// TwinCAT 3 PLC project First_Recipe_Save
// libraries:
//   Lib_FileOperation, * (Beckhoff China)
//   Tc2_Standard, * (Beckhoff Automation GmbH)
//   Tc2_Standard, * (Beckhoff Automation GmbH)
//   Tc2_System, * (Beckhoff Automation GmbH)
//   Tc2_System, * (Beckhoff Automation GmbH)
//   Tc2_Utilities, * (Beckhoff Automation GmbH)
//   Tc2_XmlDataSrv, * (Beckhoff Automation GmbH)
//   Tc3_Module, * (Beckhoff Automation GmbH)
//   Tc3_Module, * (Beckhoff Automation GmbH)
// project tree:
//   Data types/Recipe_MachineData/ ST_MachineData.TcDUT, ST_RecData.TcDUT
//   Global Variables/ Global_Variables.TcGVL, Global_Variables_Param.TcGVL, Variable_Configuration.TcGVL
//   Global Variables/Recipe_Var_and_Constant/ Recipe_Manager.TcGVL, Recipe_OtherHMI.TcGVL
//   / GlobalImagePool.TcGIPO, GlobalTextList.TcGTLO, PlcTask1.TcTTO, 视图管理器.TcVMO
//   POUs/FileOperation/File FB/Backup/ FB_MachineData_BIN.TcPOU, FB_MachineData_XML.TcPOU
//   POUs/FileOperation/File FB/ FB_MachineData.TcPOU
//   POUs/FileOperation/File PRG/ PRG_MachineDataSave.TcPOU
//   POUs/FileOperation/Recipe FB/ FB_Recipe.TcPOU, FB_Recipe_OtherHMI.TcPOU, FB_Recipe_TcPlcHMI.TcPOU
//   POUs/FileOperation/Recipe PRG/ PRG_Recipe.TcPOU, PRG_Recipe_OtherHMI.TcPOU, PRG_Recipe_TcPlcHMI.TcPOU
//   POUs/ MAIN.TcPOU, P099_Call_Recipe.TcPOU
//   Visualizations/9_FBs & FCs/Files Operation/Recipe/PH/V2/Button/ PH_RECIPE_BUTTON_DELETE_2.TcVIS, PH_RECIPE_BUTTON_FLASH_2.TcVIS, PH_RECIPE_BUTTON_FROM_USB_2.TcVIS, PH_RECIPE_BUTTON_LOAD_2.TcVIS, PH_RECIPE_BUTTON_SAVE_2.TcVIS, PH_RECIPE_BUTTON_SAVE_AS_2.TcVIS, PH_RECIPE_BUTTON_TO_USB_2.TcVIS
//   Visualizations/9_FBs & FCs/Files Operation/Recipe/PH/V2/Confirm Windows/ PH_RECIPE_CONFIRM_WINDOW_2.TcVIS
//   Visualizations/9_FBs & FCs/Files Operation/Recipe/PH/V2/Files Name/ PH_RECIPE_CURRENT_OPEN_FILE_2.TcVIS, PH_RECIPE_FILE_PATH_2.TcVIS, PH_RECIPE_LOAD_FILE_NAME_2.TcVIS, PH_RECIPE_SAVE_FILE_NAME_2.TcVIS
//   Visualizations/9_FBs & FCs/Files Operation/Recipe/PH/V2/Recipe Name/ PH_RECIPE_FILE_NAME_DISPLAY_1.TcVIS, PH_RECIPE_FILE_NAME_DISPLAY_2.TcVIS
//   Visualizations/9_FBs & FCs/Files Operation/Recipe/PH/V2/Scroll/ PH_RECIPE_PAGE_BOTTON_2.TcVIS, PH_RECIPE_PAGE_DOWN_2.TcVIS, PH_RECIPE_PAGE_TOP_2.TcVIS, PH_RECIPE_PAGE_UP_2.TcVIS, PH_RECIPE_REGULAR.TcVIS, PH_RECIPE_REGULAR_1.TcVIS, PH_RECIPE_SCROLL_DOWN_2.TcVIS, PH_RECIPE_SCROLL_UP_2.TcVIS
//   Visualizations/9_FBs & FCs/Files Operation/Recipe/ question.TcTLO, SystemDisplay.TcTLO, TextList_Recipe.TcTLO
//   Visualizations/9_FBs & FCs/Payment/ PH_PAYMENT_CTRL.TcVIS, TextList_Payment.TcTLO
//   Visualizations/Demo_Recipe_HMI/ BECKHOFF_PLC_HMI.TcVIS, THIRDPARTY_HMI.TcVIS

CONFIGURATION First_Recipe_Save
    RESOURCE PLC ON TwinCAT3
        TASK PlcTask1(INTERVAL := T#2ms, PRIORITY := 22);
        PROGRAM P099_Call_Recipe WITH PlcTask1 : P099_Call_Recipe;
    END_RESOURCE
END_CONFIGURATION

// ---- Data types/Recipe_MachineData/ST_MachineData.TcDUT
TYPE ST_MachineData :		(*机器参数, 只保存一个文件*)
STRUCT
	MacData1		: ARRAY[1..2] OF LREAL;
	MacData2		: ARRAY[1..2] OF INT;
	MacData3		: ARRAY[1..2] OF BOOL;

END_STRUCT
END_TYPE

// ---- Data types/Recipe_MachineData/ST_RecData.TcDUT
TYPE ST_RecData :			(*配方参数, 不同配方参数, 保存在不同的文件中*)
STRUCT

(*设置参数*)
	rTemp:REAL:=120;      	(*温度，120.C*)
	rSpeedRpm:REAL:=3000;(*速度，3000rpm*)
	rPressure:REAL:=9.8; (*压力，9.8kg*)

END_STRUCT
END_TYPE

// ---- Global Variables/Global_Variables.TcGVL
{attribute 'Tc2GvlVarNames'}
VAR_GLOBAL
END_VAR

// ---- Global Variables/Global_Variables_Param.TcGVL
{attribute 'Tc2GvlVarNames'}
VAR_GLOBAL
	sRecData				: ST_RecData;
	sMacData				: ST_MachineData;

(*临时变量, 和设置的参数比较, 参数修改后, 延时自动保存参数*)
(*结构体类型(数组长度)必须一致, 否则比较/复制时, 会有意想不到的错误*)
	_sRecData				: ST_RecData;
	_sMacData				: ST_MachineData;
END_VAR

// ---- Global Variables/Recipe_Var_and_Constant/Recipe_Manager.TcGVL
{attribute 'Tc2GvlVarNames'}
(*配方功能相关变量*)
VAR_GLOBAL
	g_sRecipeCtrl				: ST_RecipeCtrl_2;
END_VAR

VAR_GLOBAL CONSTANT
	MAX_RECIPE_NUM				: INT := 15;	(*配方列表中显示的文件数量*)
	MAX_RECIPE_DATA				: INT := 2;	(*配方变量(一个结构、数组只算一个变量, 离散的)*)
END_VAR

// ---- Global Variables/Recipe_Var_and_Constant/Recipe_OtherHMI.TcGVL
{attribute 'Tc2GvlVarNames'}
(*配方功能: 第三方触摸屏*)

VAR_GLOBAL CONSTANT
	MAX_FILE_NAME_STR			: INT	:= 20;	(*配方名字长度, 20个字节*)
	MAX_RECIPE_FILES			: INT	:= 5;	(*最多保存的配方数量*)
END_VAR

VAR_GLOBAL
(*配方文件(和配方号对应的)名字*)
	H_RecipeName				: ARRAY[0..MAX_RECIPE_FILES] OF STRING(MAX_FILE_NAME_STR);
END_VAR

VAR_GLOBAL
	H_CurRecipeNum				: INT;	(*当前配方号*)
	H_SetRecipeNum				: INT;	(*设定配方号, 0~100*)
(*!!!按钮, 下降沿触发!!!*)
	H_RecipeLoad				: BOOL;	(*读取设定配方号中的参数*)
	H_RecipeSave				: BOOL;	(*参数保存到当前配方号*)
	H_RecipeSaveAs				: BOOL;	(*参数保存到设定的配方号*)
(*状态*)
	H_RecipeInitialDone			: BOOL;	(*初始化完成*)
	H_RecipeDone				: BOOL;	(*读写完成*)
	H_RecipeBusy				: BOOL;	(*读写中*)
	H_RecipeError				: BOOL;	(*读写失败*)
	H_RecipeLoading				: BOOL;	(*配方读取中...*)
	H_RecipeSaving				: BOOL;	(*配方保存中...*)
	H_NewRecipeSaving			: BOOL;	(*配方另存中...*)
	H_CurDataAutoSaving			: BOOL;	(*自动保存中...*)
(*当前配方名*)
	H_CurRecName				: STRING(MAX_FILE_NAME_STR);
END_VAR

// ---- Global Variables/Variable_Configuration.TcGVL
{attribute 'Tc2GvlVarNames'}
VAR_CONFIG
END_VAR

// ---- POUs/P099_Call_Recipe.TcPOU
PROGRAM P099_Call_Recipe
VAR
	bThirdpartyHMI			: BOOL;
	iHMI: INT;
END_VAR



(*保存机器数据*)
PRG_MachineDataSave();

CASE iHMI OF

1:(*使用TwinCAT PLC HMI 操作配方*)
	PRG_Recipe_TcPlcHMI();

2:(*使用第三方触摸屏操作配方*)
	PRG_Recipe_OtherHMI();

ELSE
  (*没有配方操作的界面*)
	PRG_Recipe();

END_CASE

END_PROGRAM

// ---- POUs/FileOperation/File PRG/PRG_MachineDataSave.TcPOU
PROGRAM PRG_MachineDataSave	(*只做参数保存, 没有配方, 需要输入一个文件名(如果有重复, 会把旧文件删除, 会影响其他参数!!), 多个变量要保存成多个文件(名)!!*)
VAR
	fbMachineData		: FB_MachineData;
	eFileType			: E_FileType :=eFileType_BIN;
END_VAR

;
fbMachineData(
	bRunOnCeDevice		:= FALSE,					(* TRUE--CE系统, FALSE--非CE系统*)
	sgFilePath			:= ,						(* 文件路径, 默认是 \Data\Machine\' *)
	sgFileName			:= 'MachineData',			(* 文件名 *)
	eFileType			:= eFileType,
	pMacData			:= ADR(sMacData),			(* 机械参数首地址 *)
	pBakData			:= ADR(_sMacData),			(* 机械参数备份的首地址, 保存上一次的参数值, 用来比较参数是否有变化 *)
	nMacSize			:= SIZEOF(sMacData),		(* 机械参数总字节数 *)
	tAutoSave			:= T#10S,					(* 参数变化后, 延时保存(写文件) *)
	bInitialDone		=> ,
	bDone				=> ,
	bBusy				=> ,
	bError				=> );

END_PROGRAM

// ---- POUs/FileOperation/File FB/FB_MachineData.TcPOU
FUNCTION_BLOCK FB_MachineData
VAR_INPUT
	bRunOnCeDevice				: BOOL	:= TRUE;	(*在CE系统运行*)
	sgFilePath					: STRING(255)	:= 'Data\Machine\';	(*文件路径*)
	sgFileName					: STRING(255)	:= 'Test';			(*文件名*)
	eFileType					: E_FileType	:= eFileType_XML;	(*文件类型, 只支持 eFileType_XML 和 eFileType_BIN 两种类型*)
(*参数和备份(用来比较参数是否修改的)的类型必须一致, 把两个变量的首地址和数据长度传到功能块*)
	pMacData					: PVOID;			(*配方首地址*)
	pBakData					: PVOID;			(*配方备份数据首地址, 数据类型必须和配方一样*)
	nMacSize					: UDINT;			(*配方的字节数*)
	tAutoSave					: TIME	:= T#10S;	(*配方改变后, 延时保存*)
END_VAR
VAR_OUTPUT
(*状态*)
	bInitialDone				: BOOL;	(*初始化完成*)
	bDone						: BOOL;
	bBusy						: BOOL;
	bError						: BOOL;
END_VAR
VAR		
	eStep						: INT;
(*Last status*)
	s_sLastExecuteResult		: ST_LastExecutionResult_File;
(*FB*)
	s_fbWriteReadFileXml		: FB_WriteReadFileXML_ByAddr;
	s_fbWriteReadFileBin		: FB_WriteReadFileBIN_2;
	s_nErrorCounter				: UDINT;
(*参数改变, 延时触发写文件*)
	s_tonDataChange				: TON;
	s_bDataChange				: BOOL;
	s_bManualWriteOnce			: BOOL;
	s_fbWriteReadFile: BOOL;
END_VAR

(*==================================================================
配置
==================================================================*)
	s_tonDataChange.PT					:= tAutoSave;		(*参数修改后, 延时写入临时文件(作用是掉电保持)的时间*)


(*==================================================================
变量地址是否有误
==================================================================*)
IF pMacData = 0 OR nMacSize <= 0 OR pBakData = 0 THEN
	bInitialDone := bBusy := bDone := FALSE;
	eStep := 0;
	bError := TRUE;
	RETURN;
END_IF


(*==================================================================
判断参数是否变化, 变化后, 延时写入文件
==================================================================*)
(*参数比较, 有变化时, 延时置位s_bDataChange, 将当前参数写到临时文件中*)
IF pMacData <> 0 AND nMacSize > 0 AND pBakData <> 0 THEN
	IF MEMCMP(pBakData, pMacData, nMacSize) <> 0 THEN
		s_tonDataChange(IN := FALSE);		(*重新计时*)
		s_tonDataChange(IN := bInitialDone);	(*上载配方后, 只复制参数, 不写入临时文件*)
		MEMCPY(pBakData, pMacData, nMacSize);	(*比较不同, 重新定时, 并把数据复制到局部变量*)
	END_IF
ELSE
	bInitialDone := FALSE;
END_IF

s_tonDataChange();

s_bDataChange := FALSE;
IF s_tonDataChange.Q THEN
	s_tonDataChange(IN := FALSE);
	s_bDataChange := TRUE;
END_IF


(*保存路径*)
CASE eFileType OF
	eFileType_BIN:
		IF bRunOnCeDevice THEN
			s_fbWriteReadFileBin.sgDeviceName	:= '\Hard disk\';
		ELSE
			s_fbWriteReadFileBin.sgDeviceName	:= 'C:\';
		END_IF
			s_fbWriteReadFileBin.sgFolderName	:= sgFilePath;
			s_fbWriteReadFileBin.sgNetId		:= '';
			s_fbWriteReadFileBin.sOption.bSameAddress_RW	:= FALSE;
			s_fbWriteReadFileBin.sOption.sBinHeader.bInused	:= FALSE;
	ELSE
		IF bRunOnCeDevice THEN
			s_fbWriteReadFileXml.sgFilePath	:= '\Hard disk\';
		ELSE
			s_fbWriteReadFileXml.sgFilePath	:= 'C:\';
		END_IF
			s_fbWriteReadFileXml.sgFilePath	:= F_CreatePath(s_fbWriteReadFileXml.sgFilePath, sgFilePath, '', '');
END_CASE

(*读写流程*)
CASE eStep OF
	0:
		bDone := bError := FALSE;
		IF NOT bInitialDone THEN
			MEMSET(ADR(s_sLastExecuteResult), 0, SIZEOF(s_sLastExecuteResult));
			s_fbWriteReadFileXml(bReadFile := FALSE, bWriteFile := FALSE);
			s_fbWriteReadFileBin(bReadFile := FALSE, bWriteFile := FALSE);
			CASE eFileType OF
				eFileType_BIN:
					eStep := 100;
				ELSE
					eStep := 150;
			END_CASE
		ELSE
			IF s_bDataChange					(*数据变化后, 延时写入*)
			OR s_bManualWriteOnce THEN			(*手动写入一次(测试用)*)
				MEMSET(ADR(s_sLastExecuteResult), 0, SIZEOF(s_sLastExecuteResult));
				s_bDataChange := FALSE;
				s_bManualWriteOnce := FALSE;
				s_fbWriteReadFileXml(bReadFile := FALSE, bWriteFile := FALSE);
				s_fbWriteReadFileBin(bReadFile := FALSE, bWriteFile := FALSE);
				CASE eFileType OF
					eFileType_BIN:
						eStep := 200;
					ELSE
						eStep := 250;
				END_CASE
			END_IF
		END_IF

	100:	(*读取BIN文件*)
		s_fbWriteReadFileBin.pDestBuffer	:= pMacData;
		s_fbWriteReadFileBin.u32DestSize	:= nMacSize;
		s_fbWriteReadFileBin.sgFileName		:= sgFileName;
		s_fbWriteReadFileBin(bReadFile := TRUE);
		s_nErrorCounter					:= 0;
		eStep := 110;
	110:
		s_fbWriteReadFileBin(bReadFile := TRUE);
		IF NOT s_fbWriteReadFileBin.bBusy THEN
			IF NOT s_fbWriteReadFileBin.bError THEN
				MEMCPY(pBakData, pMacData, nMacSize);	(*读取完, 把值传给中间变量*)
				bDone := TRUE;
				eStep := 0;
			ELSE
				s_nErrorCounter := s_nErrorCounter + 1;	(*连续读写失败, 可能是文件不存在, 跳过*)
				IF s_nErrorCounter > 5 THEN
					bError := TRUE;
					eStep := 0;
				END_IF
			END_IF
			s_bDataChange := FALSE;
			s_bManualWriteOnce := FALSE;
			s_fbWriteReadFileBin(bReadFile := FALSE, bWriteFile := FALSE);
		END_IF

	150:	(*读取XML文件*)
		s_fbWriteReadFileXml.pDataADR		:= pMacData;
		s_fbWriteReadFileXml.u32DataSIZEOF	:= nMacSize;
		s_fbWriteReadFileXml.sgFileName		:= sgFileName;
		s_fbWriteReadFileXml(bReadFile := TRUE);
		s_nErrorCounter					:= 0;
		eStep := 160;
	160:
		s_fbWriteReadFileXml(bReadFile := TRUE);
		IF NOT s_fbWriteReadFileXml.bBusy THEN
			IF NOT s_fbWriteReadFileXml.bError THEN
				MEMCPY(pBakData, pMacData, nMacSize);	(*读取完, 把值传给中间变量*)
				bDone := TRUE;
				eStep := 0;
			ELSE
				s_nErrorCounter := s_nErrorCounter + 1;	(*连续读写失败, 可能是文件不存在, 跳过*)
				IF s_nErrorCounter > 5 THEN
					bError := TRUE;
					eStep := 0;
				END_IF
			END_IF
			s_bDataChange := FALSE;
			s_bManualWriteOnce := FALSE;
			s_fbWriteReadFileXml(bReadFile := FALSE, bWriteFile := FALSE);
		END_IF

	200:	(*写入BIN文件*)
		s_fbWriteReadFileBin.pSrcBuffer		:= pMacData;
		s_fbWriteReadFileBin.u32SrcSize		:= nMacSize;
		s_fbWriteReadFileBin.sgFileName		:= sgFileName;
		s_fbWriteReadFileBin(bWriteFile := TRUE);
		eStep := 210;
	210:
		s_fbWriteReadFileBin(bWriteFile := TRUE);
		IF s_fbWriteReadFileBin.bWriteFile THEN
			s_fbWriteReadFileBin(bWriteFile := TRUE);
			IF NOT s_fbWriteReadFileBin.bBusy THEN
				IF NOT s_fbWriteReadFileBin.bError THEN
					bDone := TRUE;
				ELSE
					bError := TRUE;
				END_IF
				s_fbWriteReadFileBin(bReadFile := FALSE, bWriteFile := FALSE);
				eStep := 0;
			END_IF
		END_IF
	250:	(*写入XML文件*)
		s_fbWriteReadFileXml.pDataADR		:= pMacData;
		s_fbWriteReadFileXml.u32DataSIZEOF	:= nMacSize;
		s_fbWriteReadFileXml.sgFileName		:= sgFileName;
		s_fbWriteReadFileXml(bWriteFile := TRUE);
		eStep := 260;
	260:
		s_fbWriteReadFileXml(bWriteFile := TRUE);
		IF s_fbWriteReadFileXml.bWriteFile THEN
			s_fbWriteReadFileXml(bWriteFile := TRUE);
			IF NOT s_fbWriteReadFileXml.bBusy THEN
				IF NOT s_fbWriteReadFileXml.bError THEN
					bDone := TRUE;
				ELSE
					bError := TRUE;
				END_IF
				s_fbWriteReadFileXml(bReadFile := FALSE, bWriteFile := FALSE);
				eStep := 0;
			END_IF
		END_IF
END_CASE


IF eStep <> 0 THEN
	bBusy := TRUE;
ELSE
	IF bBusy THEN
		bBusy := FALSE;
		bInitialDone := TRUE;			(*不管有没有读取成功, 都认为初始化完成*)
		s_sLastExecuteResult.bDone := bDone;
		s_sLastExecuteResult.bError := bError;
	END_IF
END_IF

END_FUNCTION_BLOCK

// ---- POUs/FileOperation/Recipe PRG/PRG_Recipe_TcPlcHMI.TcPOU
PROGRAM PRG_Recipe_TcPlcHMI	(*Twincat PLC HMI, 参数保存, 配方功能*)
VAR
	fbRecipeTcPlcHMI	: FB_Recipe_TcPlcHMI;
	eFileType			: E_FileType :=eFileType_BIN;
END_VAR


(*测试*)
VAR
	nErrorCounter			: INT;
	nDoneCounter			: INT;
END_VAR

;
fbRecipeTcPlcHMI(
	bRunOnCeDevice		:= FALSE,					(* TRUE--CE系统, FALSE--非CE系统*)
	sgFilePath			:= '\Data\Recipe\',			(* 文件路径, 默认是 \Data\Recipe\' *)
	eFileType			:= eFileType ,				(* 文件类型, 默认是XML, 只支持 eFileType_XML 和 eFileType_BIN 两种类型 *)
	pRecData			:= ADR(sRecData),			(* 配方参数首地址 *)
	pBakData			:= ADR(_sRecData),			(* 配方备份的首地址, 保存上一次的参数值, 用来比较参数是否有变化 *)
	nRecSize			:= SIZEOF(sRecData),		(* 配方总字节数 *)
	tAutoSaveRec		:= T#3S,					(* 参数变化后, 延时保存(写文件) *)
	sRecipeCtrl			:= g_sRecipeCtrl,			(* 触摸屏按钮, 配方名, 状态等等 *)
	bInitialDone		=> ,						(* 初始化完成 *)
	bDone				=> ,						(* 读写完成 *)
	bBusy				=> ,						(* 读写中 *)
	bError				=> ,						(* 读写失败 *)
	nErrorId			=> );						(* 错误代码 *)


(*测试*)
IF fbRecipeTcPlcHMI.bError THEN		(*没有作用, 要读取 LastResult.Error*)
	nErrorCounter := nErrorCounter + 1;
END_IF
IF fbRecipeTcPlcHMI.bDone THEN
	nDoneCounter := nDoneCounter + 1;
END_IF

END_PROGRAM

// ---- POUs/FileOperation/Recipe FB/FB_Recipe_TcPlcHMI.TcPOU
FUNCTION_BLOCK FB_Recipe_TcPlcHMI
VAR_INPUT
	bRunOnCeDevice				: BOOL	:= TRUE;	(*在CE系统运行*)
	sgFilePath					: STRING(255)	:= 'Data\Recipe\';	(*文件路径*)
	eFileType					: E_FileType	:= eFileType_XML;	(*文件类型, 只支持 eFileType_XML 和 eFileType_BIN 两种类型*)
(*配方和备份(用来比较配方参数是否修改的)的类型必须一致, 把两个变量的首地址和数据长度传到功能块*)
	pRecData					: PVOID;			(*配方首地址*)
	pBakData					: PVOID;			(*配方备份数据首地址, 数据类型必须和配方一样*)
	nRecSize					: UDINT;			(*配方的字节数*)
	tAutoSaveRec				: TIME	:= T#10S;	(*配方改变后, 延时保存*)
END_VAR
VAR_OUTPUT
(*状态*)
	bInitialDone				: BOOL;	(*初始化完成*)
	bDone						: BOOL;
	bBusy						: BOOL;
	bError						: BOOL;
	nErrorId					: UDINT;
END_VAR
VAR_IN_OUT
	sRecipeCtrl					: ST_RecipeCtrl_2;	(*配方相关的命令和状态*)
END_VAR
VAR
	i: INT;
(*Last status*)
	s_sLastExecuteResult		: ST_LastExecutionResult_File;
(*FB*)
	s_fbRecipeManager			: FB_RecipeManager_2;
	s_sRecipeData				: ST_RecipeData_2;
(*上载配方动作, 上载完成后, 不判断当前参数是否有改变*)
	s_ftRecipeLoad				: F_TRIG;
	s_tonLoadRecipe				: TON;
(*参数改变, 延时触发写文件*)
	s_tonDataChange				: TON;
	s_bDataChange				: BOOL;
(*配方读写时间*)
	s_tActRecipeRead			: TIME;
	s_tActRecipeWrite			: TIME;
	s_tRecipeRead				: TIME;
	s_tRecipeWrite				: TIME;
	s_tonRecipeOperation		: TON;
	s_tonRecipeNotBusy			: TON;
END_VAR

;
(*==================================================================
配置
==================================================================*)
	(*延时时间*)
	s_tonDataChange.PT					:= tAutoSaveRec;		(*参数修改后, 延时写入临时文件(作用是掉电保持)的时间*)
	s_tonLoadRecipe.PT					:= T#100MS;		(*上载配方时, 延时判断读取完成*)

	(*其他, 只针对TwinCAT PLC HMI, 第三方触摸屏的可以不设置*)
	sRecipeCtrl.i16DisplayFilesNum		:= 14;			(*Target Visualization中用到的'PH_RECIPE_FILE_NAME_DISPLAY'的数量, 如果是第三方HMI, 设置为0*)
	sRecipeCtrl.bRecipeNeedConfirm		:= TRUE;		(*上载, 保存, 删除是否需要确认. FALSE--不需要, TRUE--需要, 第三方触摸屏, 建议设置为FALSE*)	(*2020.10.10, 更改为FALSE*)
	sRecipeCtrl.bRecipeAutoRead			:= TRUE;		(*初始化时, 是否要从actRecipe中读取之前保存的参数*)
	sRecipeCtrl.bFileTypeDisplay		:= FALSE;		(*在'PH_RECIPE_FILE_NAME_DISPLAY'是否显示文件类型. FALSE--不显示, TRUE--显示*)
(*
	sRecipeCtrl.u16MaxTempFilesNum		:= 300;			(*保存300个临时文件*)
	sRecipeCtrl.u16KeepErrorFilesDay	:= 7;			(*错误文件保存7天*)
*)



(*==================================================================
变量地址是否有误
==================================================================*)
IF pRecData = 0 OR nRecSize <= 0 OR pBakData = 0 THEN
	bInitialDone := bBusy := bDone := FALSE;
	bError := TRUE;
	IF nRecSize > 0 THEN
		nErrorId := 16#5F0A;
	ELSE
		nErrorId := 16#5F0B;
	END_IF
	RETURN;
END_IF
(*变量的地址和长度*)
s_sRecipeData.stRecipeDataArr[1].pRecipeDataInfoADR			:= pRecData;
s_sRecipeData.stRecipeDataArr[1].u32RecipeDataInfoSIZEOF	:= nRecSize;
s_sRecipeData.stRecipeDataArr[1].sgRecipeDataInfoName		:= 'RecData';


(*==================================================================
判断参数是否变化, 变化后, 延时写入文件
==================================================================*)
s_tonRecipeNotBusy(IN := NOT sRecipeCtrl.sStatus.bBusy, PT := T#1S);
(*上载配方完成后, 把当前参数复制到临时参数中. 不写文件*)
s_ftRecipeLoad(CLK := sRecipeCtrl.sCmd.bRecipeLoad);
IF s_ftRecipeLoad.Q THEN
	s_tonLoadRecipe.IN := TRUE;
END_IF
s_tonLoadRecipe();
IF s_tonLoadRecipe.Q AND s_tonRecipeNotBusy.Q THEN
	s_tonLoadRecipe(IN := FALSE);
	s_tonDataChange(IN := FALSE);
END_IF

(*参数比较, 有变化时, 延时置位s_bDataChange, 将当前参数写到临时文件中*)
IF pRecData <> 0 AND nRecSize > 0 AND pBakData <> 0 THEN
	IF MEMCMP(pBakData, pRecData, nRecSize) <> 0 THEN
		s_tonDataChange(IN := FALSE);		(*重新计时*)
		s_tonDataChange(IN := sRecipeCtrl.sStatus.bInitialOk AND s_tonRecipeNotBusy.Q);	(*上载配方后, 只复制参数, 不写入临时文件*)
		MEMCPY(pBakData, pRecData, nRecSize);	(*比较不同, 重新定时, 并把数据复制到局部变量*)
	END_IF
END_IF

s_tonDataChange();
s_bDataChange := FALSE;
IF s_tonDataChange.Q AND s_tonRecipeNotBusy.Q THEN
	s_tonDataChange(IN := FALSE);
	s_bDataChange := TRUE;
END_IF

(*文件类型*)
IF eFileType = eFileType_BIN THEN
	s_fbRecipeManager.eFileType	:= eFileType_BIN;
ELSE
	s_fbRecipeManager.eFileType	:= eFileType_XML;
END_IF


(*==================================================================
调用配方程序, 根据实际情况修改文件夹路径: sgFolderName 和文件类型 eFileType
==================================================================*)
s_fbRecipeManager(
	sRecipeData				:= s_sRecipeData,		(*配方*)
	sgNetId					:= '',
	sgDeviceName			:= SEL(bRunOnCeDevice, 'C:\', '\Hard disk\'),		(*Device*)
	sgUsbDeviceName			:= SEL(bRunOnCeDevice, 'D:\', '\Hard disk2\'),		(*USB*)
	sgFolderName			:= sgFilePath,			(*文件夹, 支持多重, 写入时自动新建文件夹*)
	eFileType				:= ,					(*文件类型, 只支持 BIN 和 XML 两种类型*)
	bDataChange				:= s_bDataChange,		(*配方数据变更, 如果启用自动读取功能, 参数改变后, 会写到临时文件 actRecipe中, 掉电保持*)
	sRecipeCtrl				:= sRecipeCtrl);		(*和HMI的接口(按钮, 状态等)*)



(*记录读写时间*)
IF sRecipeCtrl.sStatus.bBusy THEN
	s_tonRecipeOperation(IN := TRUE, PT := T#1H);
	CASE s_fbRecipeManager.s_eOperateStep OF
		1..99:
			s_tActRecipeRead := s_tonRecipeOperation.ET;
		200..299:
			s_tActRecipeWrite := s_tonRecipeOperation.ET;
		300..399:
			s_tRecipeRead := s_tonRecipeOperation.ET;
		400..499:
			s_tRecipeWrite := s_tonRecipeOperation.ET;
	END_CASE
ELSE
	s_tonRecipeOperation(IN := FALSE);
	sRecipeCtrl.sStatus.bError := FALSE;
END_IF

(*状态*)
bInitialDone	:= sRecipeCtrl.sStatus.bInitialOk;	(*初始化完成*)
bError			:= sRecipeCtrl.sStatus.bError;		(*报错*)
bBusy			:= sRecipeCtrl.sStatus.bBusy;
bDone			:= sRecipeCtrl.sStatus.bDone;
nErrorId		:= sRecipeCtrl.sStatus.u32ErrorId;
(*上一次触发的状态*)
MEMCPY(ADR(s_sLastExecuteResult), ADR(s_fbRecipeManager.s_sLastExecuteResult), SIZEOF(s_sLastExecuteResult));

END_FUNCTION_BLOCK

// ---- POUs/FileOperation/Recipe PRG/PRG_Recipe_OtherHMI.TcPOU
PROGRAM PRG_Recipe_OtherHMI	(*第三方触摸屏, 参数保存, 配方功能*)
VAR
	fbRecipeOtherHMI		: FB_Recipe_OtherHMI;
	eFileType			: E_FileType :=eFileType_BIN;
END_VAR


(*测试*)
VAR
	nErrorCounter			: INT;
	nDoneCounter			: INT;
END_VAR

;
fbRecipeOtherHMI(
	bRunOnCeDevice		:= FALSE,					(* TRUE--CE系统, FALSE--非CE系统*)
	sgFilePath			:= ,						(* 文件路径, 默认是 \Data\Recipe\' *)
	eFileType			:= eFileType,						(* 文件类型, 默认是XML, 只支持 eFileType_XML 和 eFileType_BIN 两种类型 *)
	pRecData			:= ADR(sRecData),			(* 配方参数首地址 *)
	pBakData			:= ADR(_sRecData),			(* 配方备份的首地址, 保存上一次的参数值, 用来比较参数是否有变化 *)
	nRecSize			:= SIZEOF(sRecData),		(* 配方总字节数 *)
	tAutoSaveRec		:= T#10S,					(* 参数变化后, 延时保存(写文件) *)
	H_RecipeLoad		:= H_RecipeLoad,			(* 第三方触摸屏上的 读取配方 按钮 *)
	H_RecipeSave		:= H_RecipeSave,			(* 第三方触摸屏上的 保存配方 按钮 *)
	H_RecipeSaveAs		:= H_RecipeSaveAs,			(* 第三方触摸屏上的 另存配方 按钮 *)
	H_SetRecipeNum		:= H_SetRecipeNum,			(* 第三方触摸屏上的 读写配方号 *)
	H_RecipeName		:= H_RecipeName,			(* 第三方触摸屏上的 配方名(输入输出接口) *)
	H_CurRecipeNum		=> H_CurRecipeNum,			(* 当前配方号 *)
	H_CurRecName		=> H_CurRecName,			(* 当前配方名 *)
	H_RecipeInitialDone	=> H_RecipeInitialDone,		(* 初始化完成 *)
	H_RecipeDone		=> H_RecipeDone,			(* 读写完成 *)
	H_RecipeBusy		=> H_RecipeBusy,			(* 读写中 *)
	H_RecipeError		=> H_RecipeError,			(* 读写失败 *)
	H_RecipeLoading		=> H_RecipeLoading,			(* 读取配方中 *)
	H_RecipeSaving		=> H_RecipeSaving,			(* 保存配方中 *)
	H_NewRecipeSaving	=> H_NewRecipeSaving,		(* 另存配方中 *)
	H_CurDataAutoSaving	=> H_CurDataAutoSaving);	(* 自动保存中 *)


(*测试*)
IF H_RecipeError THEN
	nErrorCounter := nErrorCounter + 1;
END_IF
IF H_RecipeDone THEN
	nDoneCounter := nDoneCounter + 1;
END_IF

END_PROGRAM

// ---- POUs/FileOperation/Recipe FB/FB_Recipe_OtherHMI.TcPOU
FUNCTION_BLOCK FB_Recipe_OtherHMI
VAR_INPUT
	bRunOnCeDevice				: BOOL	:= TRUE;	(*在CE系统运行*)
	sgFilePath					: STRING(255)	:= 'Data\Recipe\';	(*文件路径*)
	eFileType					: E_FileType	:= eFileType_XML;	(*文件类型, 只支持 eFileType_XML 和 eFileType_BIN 两种类型*)
(*配方和备份(用来比较配方参数是否修改的)的类型必须一致, 把两个变量的首地址和数据长度传到功能块*)
	pRecData					: PVOID;			(*配方首地址*)
	pBakData					: PVOID;			(*配方备份数据首地址, 数据类型必须和配方一样*)
	nRecSize					: UDINT;			(*配方的字节数*)
	tAutoSaveRec				: TIME	:= T#10S;	(*配方改变后, 延时保存*)

(*按钮, 下降沿触发!!!*)
	H_RecipeLoad				: BOOL;	(*读取设定配方号中的参数*)
	H_RecipeSave				: BOOL;	(*参数保存到当前配方号*)
	H_RecipeSaveAs				: BOOL;	(*参数保存到设定的配方号*)
(*设定配方号*)
	H_SetRecipeNum				: INT	:= 1;	(*设定配方号, 1~100*)
END_VAR
VAR_OUTPUT
(*当前配方号*)
	H_CurRecipeNum				: INT;
(*配方文件(和配方号对应的)名字*)
	H_CurRecName				: STRING(20);
(*状态*)
	H_RecipeInitialDone			: BOOL;	(*初始化完成*)
	H_RecipeDone				: BOOL;	(*读写完成*)
	H_RecipeBusy				: BOOL;	(*读写中*)
	H_RecipeError				: BOOL;	(*读写失败*)
	H_RecipeLoading				: BOOL;	(*配方读取中...*)
	H_RecipeSaving				: BOOL;	(*配方保存中...*)
	H_NewRecipeSaving			: BOOL;	(*配方另存中...*)
	H_CurDataAutoSaving			: BOOL;	(*自动保存中...*)
END_VAR
VAR_IN_OUT
	H_RecipeName				: ARRAY[0..MAX_RECIPE_FILES] OF STRING(MAX_FILE_NAME_STR);	(*0存放配方号, 1~MAX, 存放配方名字*)
END_VAR
VAR
	i: INT;
(*Last status*)
	s_sLastExecuteResult		: ST_LastExecutionResult_File;
(*FB*)
	s_fbRecipeManager			: FB_RecipeManager_2;
	s_sRecipeData				: ST_RecipeData_2;
	s_sRecipeCtrl				: ST_RecipeCtrl_2;	(*配方相关的命令和状态*)
(*上载配方动作, 上载完成后, 不判断当前参数是否有改变*)
	s_ftRecipeLoad				: F_TRIG;
	s_tonLoadRecipe				: TON;
(*参数改变, 延时触发写文件*)
	s_tonDataChange				: TON;
	s_bDataChange				: BOOL;
(*配方读写时间*)
	s_tActRecipeRead			: TIME;
	s_tActRecipeWrite			: TIME;
	s_tRecipeRead				: TIME;
	s_tRecipeWrite				: TIME;
	s_tonRecipeOperation		: TON;
	s_tonRecipeNotBusy			: TON;
END_VAR
(*第三方触摸屏*)
VAR
	tpRecipeLoad				: TP;
	tpRecipeSave				: TP;
	tpNewRecipeSave				: TP;
	fbFormatString				: FB_FormatString;
	bRecipeLoading				: BOOL;
	bRecipeSaving				: BOOL;
	bNewRecipeSaving			: BOOL;
	nLoadRecipeNum				: INT;		(*当前读取配方号*)
	fbWriteReadFile				: FB_WriteReadFileXML_ByAddr;	(*保存配方文件名和ID*)
	fbWriteReadFile_Bin			: FB_WriteReadFileBIN_2;
	tpInitialOk					: TP;
	bFileReadDone				: BOOL;
(*参数改变, 延时触发写文件*)
	s_sgRecipeName				: ARRAY[0..MAX_RECIPE_FILES] OF STRING(MAX_FILE_NAME_STR);	(*0存放配方号, 1~MAX, 存放配方名字*)
	s_tonRecipeNameChange		: TON;
	s_bRecipeNameChange			: BOOL;
	s_bRecipeNameChange1		: BOOL;
END_VAR

;
(*==================================================================
配置
==================================================================*)
	(*延时时间*)
	s_tonDataChange.PT					:= tAutoSaveRec;		(*参数修改后, 延时写入临时文件(作用是掉电保持)的时间*)
	s_tonRecipeNameChange.PT			:= tAutoSaveRec;
	s_tonLoadRecipe.PT					:= T#100MS;		(*上载配方时, 延时判断读取完成*)

	(*其他, 只针对TwinCAT PLC HMI, 第三方触摸屏的可以不设置*)
	s_sRecipeCtrl.i16DisplayFilesNum	:= 14;			(*Target Visualization中用到的'PH_RECIPE_FILE_NAME_DISPLAY'的数量, 如果是第三方HMI, 设置为0*)
	s_sRecipeCtrl.bRecipeNeedConfirm	:= TRUE;		(*上载, 保存, 删除是否需要确认. FALSE--不需要, TRUE--需要, 第三方触摸屏, 建议设置为FALSE*)	(*2020.10.10, 更改为FALSE*)
	s_sRecipeCtrl.bRecipeAutoRead		:= TRUE;		(*初始化时, 是否要从actRecipe中读取之前保存的参数*)
	s_sRecipeCtrl.bFileTypeDisplay		:= FALSE;		(*在'PH_RECIPE_FILE_NAME_DISPLAY'是否显示文件类型. FALSE--不显示, TRUE--显示*)
(*
	s_sRecipeCtrl.u16MaxTempFilesNum	:= 300;			(*保存300个临时文件*)
	s_sRecipeCtrl.u16KeepErrorFilesDay	:= 7;			(*错误文件保存7天*)
*)


(*==================================================================
变量地址是否有误
==================================================================*)
IF pRecData = 0 OR nRecSize <= 0 OR pBakData = 0 THEN
	H_RecipeError						:= TRUE;
	RETURN;
END_IF
(*变量的地址和长度*)
s_sRecipeData.stRecipeDataArr[1].pRecipeDataInfoADR			:= pRecData;
s_sRecipeData.stRecipeDataArr[1].u32RecipeDataInfoSIZEOF	:= nRecSize;
s_sRecipeData.stRecipeDataArr[1].sgRecipeDataInfoName		:= 'RecData';


(*==================================================================
第三方触摸屏
==================================================================*)
s_sRecipeCtrl.bRecipeNeedConfirm	:= FALSE;		(*上载, 保存, 删除是否需要确认. FALSE--不需要, TRUE--需要, 第三方触摸屏, 建议设置为FALSE*)	(*2020.10.10, 更改为FALSE*)
(*按钮, 在HMI设置保持2s后输出, 功能块中只接收下降沿, 所以用一个脉宽输出*)
tpRecipeLoad(IN := H_RecipeLoad, PT := T#50MS);
tpRecipeSave(IN := H_RecipeSave, PT := T#50MS);
tpNewRecipeSave(IN := H_RecipeSaveAs, PT := T#50MS);
(*配方号*)
H_SetRecipeNum := LIMIT(1, H_SetRecipeNum, MAX_RECIPE_FILES);
(*获取触摸屏按钮状态, 生成文件名, 并读写文件*)
IF NOT s_sRecipeCtrl.sStatus.bBusy THEN
	(*生成文件名*)
	IF tpRecipeLoad.Q THEN			(*读取设定配方号中的参数*)
		nLoadRecipeNum := H_SetRecipeNum;
		fbFormatString(
			sFormat:= 'Recipe_%.3d',
			arg1:= F_INT(H_SetRecipeNum),
			sOut=> s_sRecipeCtrl.sgFileNameLoad);
		bRecipeLoading := TRUE;
	ELSIF tpRecipeSave.Q THEN			(*参数保存到当前配方号*)
		fbFormatString(
			sFormat:= 'Recipe_%.3d',
			arg1:= F_INT(H_CurRecipeNum),
			sOut=> s_sRecipeCtrl.sgFileNameLoad);
		bRecipeSaving := TRUE;
	ELSIF tpNewRecipeSave.Q THEN		(*参数保存到设定的配方号*)
		fbFormatString(
			sFormat:= 'Recipe_%.3d',
			arg1:= F_INT(H_SetRecipeNum),
			sOut=> s_sRecipeCtrl.sgFileNameSave);
		bNewRecipeSaving := TRUE;
	END_IF
	(*命令*)
	s_sRecipeCtrl.sCmd.bRecipeLoad		:= tpRecipeLoad.Q;
	s_sRecipeCtrl.sCmd.bRecipeSave		:= tpRecipeSave.Q;
	s_sRecipeCtrl.sCmd.bRecipeSaveAs	:= tpNewRecipeSave.Q ;
END_IF

(*状态*)
H_RecipeInitialDone	:= s_sRecipeCtrl.sStatus.bInitialOk AND bFileReadDone;	(*初始化完成*)
H_RecipeLoading		:= s_sRecipeCtrl.sStatus.bBusy AND bRecipeLoading;		(*配方读取中...*)
H_RecipeSaving		:= s_sRecipeCtrl.sStatus.bBusy AND bRecipeSaving;			(*配方保存中...*)
H_NewRecipeSaving	:= s_sRecipeCtrl.sStatus.bBusy AND bNewRecipeSaving;		(*配方另存中...*)
H_CurDataAutoSaving	:= s_sRecipeCtrl.sStatus.bBusy							(*自动保存中...*)
						AND NOT (bRecipeLoading OR bRecipeSaving OR bNewRecipeSaving);
H_RecipeBusy		:= s_sRecipeCtrl.sStatus.bBusy							(*读写中*)
						AND (bRecipeLoading OR bRecipeSaving OR bNewRecipeSaving);
H_RecipeError		:= s_sRecipeCtrl.sStatus.bError;		(*读写失败*)
H_RecipeDone		:= s_sRecipeCtrl.sStatus.bDone;		(*读写完成*)
(*上一次触发的状态*)
MEMCPY(ADR(s_sLastExecuteResult), ADR(s_fbRecipeManager.s_sLastExecuteResult), SIZEOF(s_sLastExecuteResult));


(*显示当前使用的配方名*)
MEMSET(ADR(H_CurRecName), 0, SIZEOF(H_CurRecName));
MEMCPY(ADR(H_CurRecName), ADR(H_RecipeName[H_CurRecipeNum]), LEN(H_RecipeName[H_CurRecipeNum]));

(*读取成功后, 把当前配方号改为保存配方号*)
IF H_RecipeDone THEN
	bRecipeSaving := FALSE;
	IF bNewRecipeSaving THEN		(**)
		H_RecipeName[H_SetRecipeNum] := H_RecipeName[H_CurRecipeNum];		(*另存时, 复位当前配方名到新的配方号对应的配方名*)
		bNewRecipeSaving := FALSE;
	END_IF
	IF bRecipeLoading THEN
		bRecipeLoading := FALSE;
		H_CurRecipeNum := nLoadRecipeNum;
	END_IF
END_IF



(*==================================================================
判断参数是否变化, 变化后, 延时写入文件
==================================================================*)
s_tonRecipeNotBusy(IN := NOT s_sRecipeCtrl.sStatus.bBusy, PT := T#1S);
(*上载配方完成后, 把当前参数复制到临时参数中. 不写文件*)
s_ftRecipeLoad(CLK := s_sRecipeCtrl.sCmd.bRecipeLoad);
IF s_ftRecipeLoad.Q THEN
	s_tonLoadRecipe.IN := TRUE;
END_IF
s_tonLoadRecipe();
IF s_tonLoadRecipe.Q AND s_tonRecipeNotBusy.Q THEN
	s_tonLoadRecipe(IN := FALSE);
	s_tonDataChange(IN := FALSE);
END_IF

(*参数比较, 有变化时, 延时置位s_bDataChange, 将当前参数写到临时文件中*)
IF pRecData <> 0 AND nRecSize > 0 AND pBakData <> 0 THEN
	IF MEMCMP(pBakData, pRecData, nRecSize) <> 0 THEN
		s_tonDataChange(IN := FALSE);		(*重新计时*)
		s_tonDataChange(IN := s_sRecipeCtrl.sStatus.bInitialOk AND s_tonRecipeNotBusy.Q);	(*上载配方后, 只复制参数, 不写入临时文件*)
		MEMCPY(pBakData, pRecData, nRecSize);	(*比较不同, 重新定时, 并把数据复制到局部变量*)
	END_IF
END_IF

s_tonDataChange();
s_bDataChange := FALSE;
IF s_tonDataChange.Q AND s_tonRecipeNotBusy.Q THEN
	s_tonDataChange(IN := FALSE);
	s_bDataChange := TRUE;
END_IF

(*文件类型*)
IF eFileType = eFileType_BIN THEN
	s_fbRecipeManager.eFileType	:= eFileType_BIN;
ELSE
	s_fbRecipeManager.eFileType	:= eFileType_XML;
END_IF

(*==================================================================
调用配方程序, 根据实际情况修改文件夹路径: sgFolderName 和文件类型 eFileType
==================================================================*)
s_fbRecipeManager(
	sRecipeData				:= s_sRecipeData,		(*配方*)
	sgNetId					:= '',
	sgDeviceName			:= SEL(bRunOnCeDevice, 'C:\', '\Hard disk\'),		(*Device*)
	sgUsbDeviceName			:= SEL(bRunOnCeDevice, 'D:\', '\Hard disk2\'),		(*USB*)
	sgFolderName			:= sgFilePath,			(*文件夹, 支持多重, 写入时自动新建文件夹*)
	eFileType				:= ,					(*文件类型, 只支持 BIN 和 XML 两种类型*)
	bDataChange				:= s_bDataChange,		(*配方数据变更, 如果启用自动读取功能, 参数改变后, 会写到临时文件 actRecipe中, 掉电保持*)
	sRecipeCtrl				:= s_sRecipeCtrl);		(*和HMI的接口(按钮, 状态等)*)



(*记录读写时间*)
IF s_sRecipeCtrl.sStatus.bBusy THEN
	s_tonRecipeOperation(IN := TRUE, PT := T#1H);
	CASE s_fbRecipeManager.s_eOperateStep OF
		1..99:
			s_tActRecipeRead := s_tonRecipeOperation.ET;
		200..299:
			s_tActRecipeWrite := s_tonRecipeOperation.ET;
		300..399:
			s_tRecipeRead := s_tonRecipeOperation.ET;
		400..499:
			s_tRecipeWrite := s_tonRecipeOperation.ET;
	END_CASE
ELSE
	s_tonRecipeOperation(IN := FALSE);
END_IF


(*==================================================================
保存配方号和文件名
==================================================================*)
tpInitialOk(IN := s_sRecipeCtrl.sStatus.bInitialOk, PT := T#100MS);		(*读取配方参数后, 再读取文件名*)

IF bFileReadDone THEN
	H_RecipeName[0]		:= INT_TO_STRING(H_CurRecipeNum);
ELSE
	H_CurRecipeNum		:= STRING_TO_INT(H_RecipeName[0]);
END_IF

(*配方名比较, 有变化时, 延时置位s_bRecipeNameChange, 将当前配方名写到文件中*)
FOR i := 0 TO MAX_RECIPE_FILES BY 1 DO
	IF s_sgRecipeName[i] <> H_RecipeName[i] THEN
		s_sgRecipeName[i] := H_RecipeName[i];
		s_bRecipeNameChange1 := TRUE;
	END_IF
END_FOR
IF s_bRecipeNameChange1 THEN
	s_bRecipeNameChange1 := FALSE;
	s_tonRecipeNameChange(IN := FALSE);		(*重新计时*)
	s_tonRecipeNameChange(IN := s_sRecipeCtrl.sStatus.bInitialOk AND bFileReadDone);		(*上载配方后, 只复制参数, 不写入临时文件*)
END_IF

s_tonRecipeNameChange();

IF s_tonRecipeNameChange.Q AND s_tonRecipeNotBusy.Q THEN
	s_tonRecipeNameChange(IN := FALSE);
	s_bRecipeNameChange := TRUE;
END_IF


(*保存路径*)
	fbWriteReadFile.sgFilePath			:= F_CreatePath(s_fbRecipeManager.sgDeviceName, sgFilePath, '\name\', '');
	fbWriteReadFile_Bin.sgDeviceName	:= s_fbRecipeManager.sgDeviceName;
	fbWriteReadFile_Bin.sgFolderName	:= F_CreatePath(sgFilePath, '\name\', '', '');

CASE eFileType OF
	eFileType_BIN:
		fbWriteReadFile_Bin.sOption.bSameAddress_RW		:= TRUE;
		fbWriteReadFile_Bin.sOption.sBinHeader.bInused	:= FALSE;
		fbWriteReadFile_Bin(
			sgNetId:= '',
			sgDeviceName:= ,
			sgFolderName:= ,
			sgFileName:= 'RecipeName',
			bReadFile:= tpInitialOk.Q,
			pDestBuffer:= ADR(H_RecipeName),
			u32DestSize:= SIZEOF(H_RecipeName),
			bWriteFile:= s_bRecipeNameChange,
			pSrcBuffer:= ADR(H_RecipeName),
			u32SrcSize:= SIZEOF(H_RecipeName),
			sOption:= ,
			tTimeout:= T#5S,
			bBusy=> , 
			bDone=> , 
			bError=> ,
			u32ErrorID=> ,
			u32DestMaxRow=> , 
			u32DestMaxCol=> , 
			hFile=> );

		IF NOT fbWriteReadFile_Bin.bBusy AND s_sRecipeCtrl.sStatus.bInitialOk THEN
			bFileReadDone := TRUE;
			s_bRecipeNameChange := FALSE;
		END_IF
	ELSE
		fbWriteReadFile(
			bReadFile:= tpInitialOk.Q,
			bWriteFile:= s_bRecipeNameChange,
			sgFilePath:= ,
			sgFileName:= 'RecipeName.xml',
			pDataADR:= ADR(H_RecipeName),
			u32DataSIZEOF:= SIZEOF(H_RecipeName),
			sgVarName:= 'RecipeName',
			bBusy=> ,
			bError=> ,
			bDone=> );
		
		IF NOT fbWriteReadFile.bBusy AND s_sRecipeCtrl.sStatus.bInitialOk THEN
			bFileReadDone := TRUE;
			s_bRecipeNameChange := FALSE;
		END_IF
END_CASE

END_FUNCTION_BLOCK

// ---- POUs/FileOperation/Recipe PRG/PRG_Recipe.TcPOU
PROGRAM PRG_Recipe			(*只做参数保存*)
VAR
	fbRecipe			: FB_Recipe;
	eFileType			: E_FileType :=eFileType_BIN;
END_VAR

;
fbRecipe(
	bRunOnCeDevice		:= FALSE,					(* TRUE--CE系统, FALSE--非CE系统*)
	sgFilePath			:= '\Data\Recipe\',			(* 文件路径, 默认是 \Data\Recipe\' *)
	eFileType			:= eFileType,				(* 文件类型, 默认是XML, 只支持 eFileType_XML 和 eFileType_BIN 两种类型 *)
	pRecData			:= ADR(sRecData),			(* 配方参数首地址 *)
	pBakData			:= ADR(_sRecData),			(* 配方备份的首地址, 保存上一次的参数值, 用来比较参数是否有变化 *)
	nRecSize			:= SIZEOF(sRecData),		(* 配方总字节数 *)
	tAutoSaveRec		:= T#3S,					(* 参数变化后, 延时保存(写文件) *)
	bInitialDone		=> ,						(* 初始化完成 *)
	bDone				=> ,						(* 读写完成 *)
	bBusy				=> ,						(* 读写中 *)
	bError				=> ,						(* 读写失败 *)
	nErrorId			=> );						(* 错误代码 *)

END_PROGRAM

// ---- POUs/FileOperation/Recipe FB/FB_Recipe.TcPOU
FUNCTION_BLOCK FB_Recipe
VAR_INPUT
	bRunOnCeDevice				: BOOL	:= TRUE;	(*在CE系统运行*)
	sgFilePath					: STRING(255)	:= 'Data\Recipe\';	(*文件路径*)
	eFileType					: E_FileType	:= eFileType_XML;	(*文件类型, 只支持 eFileType_XML 和 eFileType_BIN 两种类型*)
(*配方和备份(用来比较配方参数是否修改的)的类型必须一致, 把两个变量的首地址和数据长度传到功能块*)
	pRecData					: PVOID;			(*配方首地址*)
	pBakData					: PVOID;			(*配方备份数据首地址, 数据类型必须和配方一样*)
	nRecSize					: UDINT;			(*配方的字节数*)
	tAutoSaveRec				: TIME	:= T#10S;	(*配方改变后, 延时保存*)
END_VAR
VAR_OUTPUT
(*状态*)
	bInitialDone				: BOOL;	(*初始化完成*)
	bDone						: BOOL;
	bBusy						: BOOL;
	bError						: BOOL;
	nErrorId					: UDINT;
END_VAR
VAR
	i: INT;
(*Last status*)
	s_sLastExecuteResult		: ST_LastExecutionResult_File;
(*FB*)
	s_fbRecipeManager			: FB_RecipeManager_2;
	s_sRecipeData				: ST_RecipeData_2;
	s_sRecipeCtrl				: ST_RecipeCtrl_2;	(*配方相关的命令和状态*)
(*上载配方动作, 上载完成后, 不判断当前参数是否有改变*)
	s_ftRecipeLoad				: F_TRIG;
	s_tonLoadRecipe				: TON;
	s_bRecipeLoad				: BOOL;
(*参数改变, 延时触发写文件*)
	s_tonDataChange				: TON;
	s_bDataChange				: BOOL;
(*配方读写时间*)
	s_tActRecipeRead			: TIME;
	s_tActRecipeWrite			: TIME;
	s_tRecipeRead				: TIME;
	s_tRecipeWrite				: TIME;
	s_tonRecipeOperation		: TON;
	s_tonRecipeNotBusy			: TON;
END_VAR

(*
自定义错误代码
16#5F0A		数据缓冲区地址有误(备用)
16#5F0B		数据缓冲区字节数有误(备用)
*)

;
(*==================================================================
配置
==================================================================*)
	(*延时时间*)
	s_tonDataChange.PT					:= tAutoSaveRec;		(*参数修改后, 延时写入临时文件(作用是掉电保持)的时间*)
	s_tonLoadRecipe.PT					:= T#100MS;		(*上载配方时, 延时判断读取完成*)

	(*其他, 只针对TwinCAT PLC HMI, 第三方触摸屏的可以不设置*)
	s_sRecipeCtrl.i16DisplayFilesNum	:= 14;			(*Target Visualization中用到的'PH_RECIPE_FILE_NAME_DISPLAY'的数量, 如果是第三方HMI, 设置为0*)
	s_sRecipeCtrl.bRecipeNeedConfirm	:= TRUE;		(*上载, 保存, 删除是否需要确认. FALSE--不需要, TRUE--需要, 第三方触摸屏, 建议设置为FALSE*)	(*2020.10.10, 更改为FALSE*)
	s_sRecipeCtrl.bRecipeAutoRead		:= TRUE;		(*初始化时, 是否要从actRecipe中读取之前保存的参数*)
	s_sRecipeCtrl.bFileTypeDisplay		:= FALSE;		(*在'PH_RECIPE_FILE_NAME_DISPLAY'是否显示文件类型. FALSE--不显示, TRUE--显示*)
(*
	s_sRecipeCtrl.u16MaxTempFilesNum	:= 300;			(*保存300个临时文件*)
	s_sRecipeCtrl.u16KeepErrorFilesDay	:= 7;			(*错误文件保存7天*)
*)

(*==================================================================
变量地址是否有误
==================================================================*)
IF pRecData = 0 OR nRecSize <= 0 OR pBakData = 0 THEN
	bInitialDone := bBusy := bDone := FALSE;
	bError := TRUE;
	IF nRecSize > 0 THEN
		nErrorId := 16#5F0A;
	ELSE
		nErrorId := 16#5F0B;
	END_IF
	RETURN;
END_IF
(*变量的地址和长度*)
s_sRecipeData.stRecipeDataArr[1].pRecipeDataInfoADR			:= pRecData;
s_sRecipeData.stRecipeDataArr[1].u32RecipeDataInfoSIZEOF	:= nRecSize;
s_sRecipeData.stRecipeDataArr[1].sgRecipeDataInfoName		:= 'RecData';


(*==================================================================
判断参数是否变化, 变化后, 延时写入文件
==================================================================*)
s_tonRecipeNotBusy(IN := NOT s_sRecipeCtrl.sStatus.bBusy, PT := T#1S);
(*上载配方完成后, 把当前参数复制到临时参数中. 不写文件*)
s_ftRecipeLoad(CLK := s_sRecipeCtrl.sCmd.bRecipeLoad);
IF s_ftRecipeLoad.Q THEN
	s_tonLoadRecipe.IN := TRUE;
END_IF
s_tonLoadRecipe();
IF s_tonLoadRecipe.Q AND s_tonRecipeNotBusy.Q THEN
	s_bRecipeLoad := TRUE;
	s_tonLoadRecipe(IN := FALSE);
	s_tonDataChange(IN := FALSE);
END_IF

(*参数比较, 有变化时, 延时置位s_bDataChange, 将当前参数写到临时文件中*)
IF pRecData <> 0 AND nRecSize > 0 AND pBakData <> 0 THEN
	IF MEMCMP(pBakData, pRecData, nRecSize) <> 0 THEN
		s_tonDataChange(IN := FALSE);		(*重新计时*)
		s_tonDataChange(IN := s_sRecipeCtrl.sStatus.bInitialOk AND NOT s_bRecipeLoad);	(*上载配方后, 只复制参数, 不写入临时文件*)
		MEMCPY(pBakData, pRecData, nRecSize);	(*比较不同, 重新定时, 并把数据复制到局部变量*)
	END_IF
ELSE
	s_bRecipeLoad := FALSE;
END_IF

s_tonDataChange();
s_bDataChange := FALSE;
IF s_tonDataChange.Q AND s_tonRecipeNotBusy.Q THEN
	s_tonDataChange(IN := FALSE);
	s_bDataChange := TRUE;
END_IF

(*文件类型*)
IF eFileType = eFileType_BIN THEN
	s_fbRecipeManager.eFileType	:= eFileType_BIN;
ELSE
	s_fbRecipeManager.eFileType	:= eFileType_XML;
END_IF

(*==================================================================
调用配方程序, 根据实际情况修改文件夹路径: sgFolderName 和文件类型 eFileType
==================================================================*)
s_fbRecipeManager(
	sRecipeData				:= s_sRecipeData,		(*配方*)
	sgNetId					:= '',
	sgDeviceName			:= SEL(bRunOnCeDevice, 'C:\', '\Hard disk\'),		(*Device*)
	sgUsbDeviceName			:= SEL(bRunOnCeDevice, 'D:\', '\Hard disk2\'),		(*USB*)
	sgFolderName			:= sgFilePath,			(*文件夹, 支持多重, 写入时自动新建文件夹*)
	eFileType				:= ,					(*文件类型, 只支持 BIN 和 XML 两种类型*)
	bDataChange				:= s_bDataChange,		(*配方数据变更, 如果启用自动读取功能, 参数改变后, 会写到临时文件 actRecipe中, 掉电保持*)
	sRecipeCtrl				:= s_sRecipeCtrl);		(*和HMI的接口(按钮, 状态等)*)



(*记录读写时间*)
IF s_sRecipeCtrl.sStatus.bBusy THEN
	s_tonRecipeOperation(IN := TRUE, PT := T#1H);
	CASE s_fbRecipeManager.s_eOperateStep OF
		1..99:
			s_tActRecipeRead := s_tonRecipeOperation.ET;
		200..299:
			s_tActRecipeWrite := s_tonRecipeOperation.ET;
		300..399:
			s_tRecipeRead := s_tonRecipeOperation.ET;
		400..499:
			s_tRecipeWrite := s_tonRecipeOperation.ET;
	END_CASE
ELSE
	s_tonRecipeOperation(IN := FALSE);
END_IF

(*状态*)
bInitialDone	:= s_sRecipeCtrl.sStatus.bInitialOk;	(*初始化完成*)
bError			:= s_sRecipeCtrl.sStatus.bError;		(*报错*)
bBusy			:= s_sRecipeCtrl.sStatus.bBusy;
bDone			:= s_sRecipeCtrl.sStatus.bDone;
nErrorId		:= s_sRecipeCtrl.sStatus.u32ErrorId;
(*上一次触发的状态*)
MEMCPY(ADR(s_sLastExecuteResult), ADR(s_fbRecipeManager.s_sLastExecuteResult), SIZEOF(s_sLastExecuteResult));

END_FUNCTION_BLOCK

// ---- POUs/FileOperation/File FB/Backup/FB_MachineData_BIN.TcPOU
FUNCTION_BLOCK FB_MachineData_BIN
VAR_INPUT
	bRunOnCeDevice				: BOOL	:= TRUE;	(*在CE系统运行*)
	sgFilePath					: STRING(255)	:= 'Data\Machine\';	(*文件路径*)
	sgFileName					: STRING(255)	:= 'Test';			(*文件名*)
(*参数和备份(用来比较参数是否修改的)的类型必须一致, 把两个变量的首地址和数据长度传到功能块*)
	pMacData					: PVOID;			(*配方首地址*)
	pBakData					: PVOID;			(*配方备份数据首地址, 数据类型必须和配方一样*)
	nMacSize					: UDINT;			(*配方的字节数*)
	tAutoSave					: TIME	:= T#10S;	(*配方改变后, 延时保存*)
END_VAR
VAR_OUTPUT
(*状态*)
	bInitialDone				: BOOL;	(*初始化完成*)
	bDone						: BOOL;
	bBusy						: BOOL;
	bError						: BOOL;
END_VAR
VAR		
	eStep						: INT;
(*Last status*)
	s_sLastExecuteResult		: ST_LastExecutionResult_File;
(*FB*)
	s_fbWriteReadFile			: FB_WriteReadFileBIN_2;
	s_nErrorCounter				: UDINT;
(*参数改变, 延时触发写文件*)
	s_tonDataChange				: TON;
	s_bDataChange				: BOOL;
	s_bManualWriteOnce			: BOOL;
END_VAR

(*==================================================================
配置
==================================================================*)
	s_tonDataChange.PT					:= tAutoSave;		(*参数修改后, 延时写入临时文件(作用是掉电保持)的时间*)


(*==================================================================
变量地址是否有误
==================================================================*)
IF pMacData = 0 OR nMacSize <= 0 OR pBakData = 0 THEN
	bInitialDone := bBusy := bDone := FALSE;
	eStep := 0;
	bError := TRUE;
	RETURN;
END_IF


(*==================================================================
判断参数是否变化, 变化后, 延时写入文件
==================================================================*)
(*参数比较, 有变化时, 延时置位s_bDataChange, 将当前参数写到临时文件中*)
IF pMacData <> 0 AND nMacSize > 0 AND pBakData <> 0 THEN
	IF MEMCMP(pBakData, pMacData, nMacSize) <> 0 THEN
		s_tonDataChange(IN := FALSE);		(*重新计时*)
		s_tonDataChange(IN := bInitialDone);	(*上载配方后, 只复制参数, 不写入临时文件*)
		MEMCPY(pBakData, pMacData, nMacSize);	(*比较不同, 重新定时, 并把数据复制到局部变量*)
	END_IF
ELSE
	bInitialDone := FALSE;
END_IF

s_tonDataChange();

s_bDataChange := FALSE;
IF s_tonDataChange.Q THEN
	s_tonDataChange(IN := FALSE);
	s_bDataChange := TRUE;
END_IF


(*保存路径*)
IF bRunOnCeDevice THEN
	s_fbWriteReadFile.sgDeviceName	:= '\Hard disk\';
ELSE
	s_fbWriteReadFile.sgDeviceName	:= 'C:\';
END_IF
	s_fbWriteReadFile.sgFolderName	:= sgFilePath;
	s_fbWriteReadFile.sgNetId		:= '';
	s_fbWriteReadFile.sOption.bSameAddress_RW		:= FALSE;
	s_fbWriteReadFile.sOption.sBinHeader.bInused	:= FALSE;


(*读写流程*)
CASE eStep OF
	0:
		bDone := bError := FALSE;
		IF NOT bInitialDone THEN
			MEMSET(ADR(s_sLastExecuteResult), 0, SIZEOF(s_sLastExecuteResult));
			s_fbWriteReadFile(bReadFile := FALSE, bWriteFile := FALSE);
			eStep := 100;
		ELSE
			IF s_bDataChange					(*数据变化后, 延时写入*)
			OR s_bManualWriteOnce THEN			(*手动写入一次(测试用)*)
				MEMSET(ADR(s_sLastExecuteResult), 0, SIZEOF(s_sLastExecuteResult));
				s_bDataChange := FALSE;
				s_bManualWriteOnce := FALSE;
				s_fbWriteReadFile(bReadFile := FALSE, bWriteFile := FALSE);
				eStep := 200;
			END_IF
		END_IF

	100:	(*读取文件, 循环, 一直判断是否需要读取, 知道最大数量*)
		s_fbWriteReadFile.pDestBuffer	:= pMacData;
		s_fbWriteReadFile.u32DestSize	:= nMacSize;
		s_fbWriteReadFile.sgFileName	:= sgFileName;
		s_fbWriteReadFile(bReadFile := TRUE);
		s_nErrorCounter					:= 0;
		eStep := 150;
	150:
		s_fbWriteReadFile(bReadFile := TRUE);
		IF NOT s_fbWriteReadFile.bBusy THEN
			IF NOT s_fbWriteReadFile.bError THEN
				MEMCPY(pBakData, pMacData, nMacSize);	(*读取完, 把值传给中间变量*)
				bDone := TRUE;
				eStep := 0;
			ELSE
				s_nErrorCounter := s_nErrorCounter + 1;	(*连续读写失败, 可能是文件不存在, 跳过*)
				IF s_nErrorCounter > 5 THEN
					bError := TRUE;
					eStep := 0;
				END_IF
			END_IF
			s_bDataChange := FALSE;
			s_bManualWriteOnce := FALSE;
			s_fbWriteReadFile(bReadFile := FALSE, bWriteFile := FALSE);
		END_IF
	200:
		s_fbWriteReadFile.pSrcBuffer	:= pMacData;
		s_fbWriteReadFile.u32SrcSize	:= nMacSize;
		s_fbWriteReadFile.sgFileName	:= sgFileName;
		s_fbWriteReadFile(bWriteFile := TRUE);
		eStep := 250;
	250:
		s_fbWriteReadFile(bWriteFile := TRUE);
		IF s_fbWriteReadFile.bWriteFile THEN
			s_fbWriteReadFile(bWriteFile := TRUE);
			IF NOT s_fbWriteReadFile.bBusy THEN
				IF NOT s_fbWriteReadFile.bError THEN
					bDone := TRUE;
				ELSE
					bError := TRUE;
				END_IF
				s_fbWriteReadFile(bReadFile := FALSE, bWriteFile := FALSE);
				eStep := 0;
			END_IF
		END_IF
END_CASE


IF eStep <> 0 THEN
	bBusy := TRUE;
ELSE
	IF bBusy THEN
		bBusy := FALSE;
		bInitialDone := TRUE;			(*不管有没有读取成功, 都认为初始化完成*)
		s_sLastExecuteResult.bDone := bDone;
		s_sLastExecuteResult.bError := bError;
	END_IF
END_IF

END_FUNCTION_BLOCK

// ---- POUs/FileOperation/File FB/Backup/FB_MachineData_XML.TcPOU
FUNCTION_BLOCK FB_MachineData_XML
VAR_INPUT
	bRunOnCeDevice				: BOOL	:= TRUE;	(*在CE系统运行*)
	sgFilePath					: STRING(255)	:= 'Data\Machine\';	(*文件路径*)
	sgFileName					: STRING(255)	:= 'Test';			(*文件名*)
(*参数和备份(用来比较参数是否修改的)的类型必须一致, 把两个变量的首地址和数据长度传到功能块*)
	pMacData					: PVOID;			(*配方首地址*)
	pBakData					: PVOID;			(*配方备份数据首地址, 数据类型必须和配方一样*)
	nMacSize					: UDINT;			(*配方的字节数*)
	tAutoSave					: TIME	:= T#10S;	(*配方改变后, 延时保存*)
END_VAR
VAR_OUTPUT
(*状态*)
	bInitialDone				: BOOL;	(*初始化完成*)
	bDone						: BOOL;
	bBusy						: BOOL;
	bError						: BOOL;
END_VAR
VAR		
	eStep						: INT;
(*Last status*)
	s_sLastExecuteResult		: ST_LastExecutionResult_File;
(*FB*)
	s_fbWriteReadFile			: FB_WriteReadFileXML_ByAddr;
	s_nErrorCounter				: UDINT;
(*参数改变, 延时触发写文件*)
	s_tonDataChange				: TON;
	s_bDataChange				: BOOL;
	s_bManualWriteOnce			: BOOL;
END_VAR

(*==================================================================
配置
==================================================================*)
	s_tonDataChange.PT					:= tAutoSave;		(*参数修改后, 延时写入临时文件(作用是掉电保持)的时间*)


(*==================================================================
变量地址是否有误
==================================================================*)
IF pMacData = 0 OR nMacSize <= 0 OR pBakData = 0 THEN
	bInitialDone := bBusy := bDone := FALSE;
	eStep := 0;
	bError := TRUE;
	RETURN;
END_IF


(*==================================================================
判断参数是否变化, 变化后, 延时写入文件
==================================================================*)
(*参数比较, 有变化时, 延时置位s_bDataChange, 将当前参数写到临时文件中*)
IF pMacData <> 0 AND nMacSize > 0 AND pBakData <> 0 THEN
	IF MEMCMP(pBakData, pMacData, nMacSize) <> 0 THEN
		s_tonDataChange(IN := FALSE);		(*重新计时*)
		s_tonDataChange(IN := bInitialDone);	(*上载配方后, 只复制参数, 不写入临时文件*)
		MEMCPY(pBakData, pMacData, nMacSize);	(*比较不同, 重新定时, 并把数据复制到局部变量*)
	END_IF
ELSE
	bInitialDone := FALSE;
END_IF

s_tonDataChange();

s_bDataChange := FALSE;
IF s_tonDataChange.Q THEN
	s_tonDataChange(IN := FALSE);
	s_bDataChange := TRUE;
END_IF


(*保存路径*)
IF bRunOnCeDevice THEN
	s_fbWriteReadFile.sgFilePath	:= '\Hard disk\';
ELSE
	s_fbWriteReadFile.sgFilePath	:= 'C:\';
END_IF
	s_fbWriteReadFile.sgFilePath	:= F_CreatePath(s_fbWriteReadFile.sgFilePath, sgFilePath, '', '');


(*读写流程*)
CASE eStep OF
	0:
		bDone := bError := FALSE;
		IF NOT bInitialDone THEN
			MEMSET(ADR(s_sLastExecuteResult), 0, SIZEOF(s_sLastExecuteResult));
			s_fbWriteReadFile(bReadFile := FALSE, bWriteFile := FALSE);
			eStep := 100;
		ELSE
			IF s_bDataChange					(*数据变化后, 延时写入*)
			OR s_bManualWriteOnce THEN			(*手动写入一次(测试用)*)
				MEMSET(ADR(s_sLastExecuteResult), 0, SIZEOF(s_sLastExecuteResult));
				s_bDataChange := FALSE;
				s_bManualWriteOnce := FALSE;
				s_fbWriteReadFile(bReadFile := FALSE, bWriteFile := FALSE);
				eStep := 200;
			END_IF
		END_IF

	100:	(*读取文件, 循环, 一直判断是否需要读取, 知道最大数量*)
		s_fbWriteReadFile.pDataADR		:= pMacData;
		s_fbWriteReadFile.u32DataSIZEOF	:= nMacSize;
		s_fbWriteReadFile.sgFileName	:= sgFileName;
		s_fbWriteReadFile(bReadFile := TRUE);
		s_nErrorCounter					:= 0;
		eStep := 150;
	150:
		s_fbWriteReadFile(bReadFile := TRUE);
		IF NOT s_fbWriteReadFile.bBusy THEN
			IF NOT s_fbWriteReadFile.bError THEN
				MEMCPY(pBakData, pMacData, nMacSize);	(*读取完, 把值传给中间变量*)
				bDone := TRUE;
				eStep := 0;
			ELSE
				s_nErrorCounter := s_nErrorCounter + 1;	(*连续读写失败, 可能是文件不存在, 跳过*)
				IF s_nErrorCounter > 5 THEN
					bError := TRUE;
					eStep := 0;
				END_IF
			END_IF
			s_bDataChange := FALSE;
			s_bManualWriteOnce := FALSE;
			s_fbWriteReadFile(bReadFile := FALSE, bWriteFile := FALSE);
		END_IF
	200:
		s_fbWriteReadFile.pDataADR		:= pMacData;
		s_fbWriteReadFile.u32DataSIZEOF	:= nMacSize;
		s_fbWriteReadFile.sgFileName	:= sgFileName;
		s_fbWriteReadFile(bWriteFile := TRUE);
		eStep := 250;
	250:
		s_fbWriteReadFile(bWriteFile := TRUE);
		IF s_fbWriteReadFile.bWriteFile THEN
			s_fbWriteReadFile(bWriteFile := TRUE);
			IF NOT s_fbWriteReadFile.bBusy THEN
				IF NOT s_fbWriteReadFile.bError THEN
					bDone := TRUE;
				ELSE
					bError := TRUE;
				END_IF
				s_fbWriteReadFile(bReadFile := FALSE, bWriteFile := FALSE);
				eStep := 0;
			END_IF
		END_IF
END_CASE


IF eStep <> 0 THEN
	bBusy := TRUE;
ELSE
	IF bBusy THEN
		bBusy := FALSE;
		bInitialDone := TRUE;			(*不管有没有读取成功, 都认为初始化完成*)
		s_sLastExecuteResult.bDone := bDone;
		s_sLastExecuteResult.bError := bError;
	END_IF
END_IF

END_FUNCTION_BLOCK

// ---- POUs/MAIN.TcPOU
PROGRAM MAIN
VAR
END_VAR

P099_Call_Recipe();

END_PROGRAM

// ---- GlobalTextList.TcGTLO
TEXTLIST GlobalTextList
  282 = '\n    第三方\n    触摸屏'
  294 = ' '
  286 = '   当前配方号:'
  288 = '   读取/另存配方号:'
  980 = '  %i'
  209 = '  %s'
  978 = '  Massage'
  293 = '  当前配方名:\n      %s'
  776 = ' 上载配方名:'
  435 = ' 另存配方名:'
  94 = ' 当前配方名:'
  111 = ' 配方保存路径:'
  266 = '%.1f'
  287 = '%i'
  818 = '%s'
  210 = '%s  '
  289 = 'B'
  50 = 'Chinese'
  290 = 'D'
  291 = 'E'
  989 = 'English'
  292 = 'I'
  480 = 'Password'
  979 = 'PaymentSetting'
  977 = 'PaymentState'
  860 = 'rPressure'
  0 = 'rSpeedRpm'
  594 = 'rTemp'
  192 = 'sRecData.rSpeedRpm'
  690 = 'TEST'
  268 = '上载并激活'
  251 = '从USB导入'
  927 = '保存'
  284 = '保存配方'
  390 = '倍福触摸屏'
  283 = '切换配方'
  933 = '删除'
  592 = '刷新'
  904 = '取消'
  227 = '另存为...'
  885 = '导出到USB'
  529 = '无触摸屏'
  903 = '确定'
  175 = '第三方触摸屏'
  642 = '说明：\n I：初始化完成\nB：读写配方中\nD：读写完成\nE：读写错误\n\n           保存：当前参数保存到当前配方号中。\n切换、读取：读取设定的配方号文件。\n           另存：当前参数另存到设定的配方号文件。'
  641 = '读取时，把配方名数组中对应设定配方号的名字，\n读取到当前配方名。\n\n另存时，把配方名数组中，对应的当前配方名，\n另存到设定的配方号对应的名字。\n\n另存后，再在数组中修改对应配方号的名字'
  174 = '配方初始化完成'
  285 = '配方另存为'
  176 = '默认是CE控制器，如果是非CE控制器（WIN7，WIN10），把功能块接口：bRunOnCeDevice 改为FALSE\n\n配方保存默认路径是（在功能块接口：sgFilePath 修改路径）\n    CE系统：    \\Hard Disk\\Data\\Recipe\n    非CE系统：C:\\Data\\Recipe\n\n文件保存默认路径是（在功能块接口：sgFilePath 修改路径）\n    CE系统：    \\Hard Disk\\Data\\Machine\n    非CE系统：C:\\Data\\Machine\n\n默认的文件类型是XML（在功能块接口：eFileType 修改类型）'
END_TEXTLIST

// ---- Visualizations/9_FBs & FCs/Files Operation/Recipe/PH/V2/Button/PH_RECIPE_BUTTON_DELETE_2.TcVIS
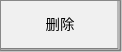
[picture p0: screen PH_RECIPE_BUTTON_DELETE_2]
VISUALIZATION PH_RECIPE_BUTTON_DELETE_2  // 122x52
VAR_IN_OUT
	RECIPE_CTRL_V2 : ST_RecipeCtrl_2;
END_VAR
    Button (0,0 120x50), "删除", input disabled if: (RECIPE_CTRL_V2.sStatus.bBusy) <> 0, text list: 'TextList_Recipe', text index: 114
        p55702900: SEL(RECIPE_CTRL_V2.sCmd.bRecipeDel, 16#000000, 16#00FF00)
        tap RECIPE_CTRL_V2.sCmd.bRecipeDel
END_VISUALIZATION

// ---- Visualizations/9_FBs & FCs/Files Operation/Recipe/PH/V2/Button/PH_RECIPE_BUTTON_FLASH_2.TcVIS
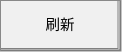
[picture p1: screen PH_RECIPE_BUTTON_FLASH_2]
VISUALIZATION PH_RECIPE_BUTTON_FLASH_2  // 122x52
VAR_IN_OUT
	RECIPE_CTRL_V2 : ST_RecipeCtrl_2;
END_VAR
    Button (0,0 120x50), "刷新", input disabled if: (RECIPE_CTRL_V2.sStatus.bBusy) <> 0, text list: 'TextList_Recipe', text index: 110
        p55702900: SEL(RECIPE_CTRL_V2.sCmd.bFlash, 16#000000, 16#00FF00)
        tap RECIPE_CTRL_V2.sCmd.bFlash
END_VISUALIZATION

// ---- Visualizations/9_FBs & FCs/Files Operation/Recipe/PH/V2/Button/PH_RECIPE_BUTTON_FROM_USB_2.TcVIS
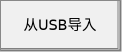
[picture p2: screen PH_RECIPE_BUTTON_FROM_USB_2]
VISUALIZATION PH_RECIPE_BUTTON_FROM_USB_2  // 122x52
VAR_IN_OUT
	RECIPE_CTRL_V2 : ST_RecipeCtrl_2;
END_VAR
    Button (0,0 120x50), "从USB导入", input disabled if: (RECIPE_CTRL_V2.sStatus.bBusy) <> 0, text list: 'TextList_Recipe', text index: 119
        p55702900: SEL(RECIPE_CTRL_V2.sCmd.bRecipeLoadFromUSB, 16#000000, 16#00FF00)
        tap RECIPE_CTRL_V2.sCmd.bRecipeLoadFromUSB
END_VISUALIZATION

// ---- Visualizations/9_FBs & FCs/Files Operation/Recipe/PH/V2/Button/PH_RECIPE_BUTTON_LOAD_2.TcVIS
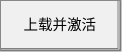
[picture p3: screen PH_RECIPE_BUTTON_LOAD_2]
VISUALIZATION PH_RECIPE_BUTTON_LOAD_2  // 122x52
VAR_IN_OUT
	RECIPE_CTRL_V2 : ST_RecipeCtrl_2;
END_VAR
    Button (0,0 120x50), "上载并激活", input disabled if: (RECIPE_CTRL_V2.sStatus.bBusy) <> 0, text list: 'TextList_Recipe', text index: 111
        p55702900: SEL(RECIPE_CTRL_V2.sCmd.bRecipeLoad, 16#000000, 16#00FF00)
        tap RECIPE_CTRL_V2.sCmd.bRecipeLoad
END_VISUALIZATION

// ---- Visualizations/9_FBs & FCs/Files Operation/Recipe/PH/V2/Button/PH_RECIPE_BUTTON_SAVE_2.TcVIS
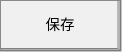
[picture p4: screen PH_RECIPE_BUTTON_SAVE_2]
VISUALIZATION PH_RECIPE_BUTTON_SAVE_2  // 122x52
VAR_IN_OUT
	RECIPE_CTRL_V2 : ST_RecipeCtrl_2;
END_VAR
    Button (0,0 120x50), "保存", input disabled if: (RECIPE_CTRL_V2.sStatus.bBusy) <> 0, text list: 'TextList_Recipe', text index: 112
        p55702900: SEL(RECIPE_CTRL_V2.sCmd.bRecipeSave, 16#000000, 16#00FF00)
        tap RECIPE_CTRL_V2.sCmd.bRecipeSave
END_VISUALIZATION

// ---- Visualizations/9_FBs & FCs/Files Operation/Recipe/PH/V2/Button/PH_RECIPE_BUTTON_SAVE_AS_2.TcVIS
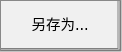
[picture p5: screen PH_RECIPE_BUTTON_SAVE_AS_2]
VISUALIZATION PH_RECIPE_BUTTON_SAVE_AS_2  // 122x52
VAR_IN_OUT
	RECIPE_CTRL_V2 : ST_RecipeCtrl_2;
END_VAR
    Button (0,0 120x50), "另存为...", input disabled if: (RECIPE_CTRL_V2.sStatus.bBusy) <> 0, text list: 'TextList_Recipe', text index: 113
        p55702900: SEL(RECIPE_CTRL_V2.sCmd.bRecipeSaveAs, 16#000000, 16#00FF00)
        tap RECIPE_CTRL_V2.sCmd.bRecipeSaveAs
END_VISUALIZATION

// ---- Visualizations/9_FBs & FCs/Files Operation/Recipe/PH/V2/Button/PH_RECIPE_BUTTON_TO_USB_2.TcVIS
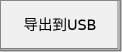
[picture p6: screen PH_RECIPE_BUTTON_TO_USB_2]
VISUALIZATION PH_RECIPE_BUTTON_TO_USB_2  // 122x52
VAR_IN_OUT
	RECIPE_CTRL_V2 : ST_RecipeCtrl_2;
END_VAR
    Button (0,0 120x50), "导出到USB", input disabled if: (RECIPE_CTRL_V2.sStatus.bBusy) <> 0, text list: 'TextList_Recipe', text index: 118
        p55702900: SEL(RECIPE_CTRL_V2.sCmd.bRecipeSaveToUSB, 16#000000, 16#00FF00)
        tap RECIPE_CTRL_V2.sCmd.bRecipeSaveToUSB
END_VISUALIZATION

// ---- Visualizations/9_FBs & FCs/Files Operation/Recipe/PH/V2/Confirm Windows/PH_RECIPE_CONFIRM_WINDOW_2.TcVIS
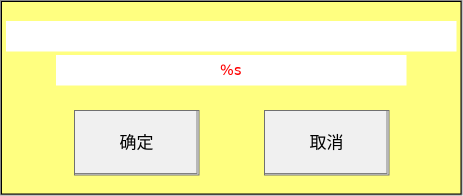
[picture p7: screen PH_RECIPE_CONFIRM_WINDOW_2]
VISUALIZATION PH_RECIPE_CONFIRM_WINDOW_2  // 463x196
VAR_IN_OUT
	RECIPE_CTRL_V2 : ST_RecipeCtrl_2;
END_VAR
    Group (1,1 460x193), invisible if: NOT RECIPE_CTRL_V2.sStatus.bShowDialog
        Rectangle (0,0 460x193), colour toggle: (RECIPE_CTRL_V2.sStatus.bFlashLamp) <> 0
        Rectangle (5,20 450x30), text list: 'question', text index: RECIPE_CTRL_V2.sStatus.i16ShowDiagID
            p2738717112: SEL(RECIPE_CTRL_V2.sStatus.sgShowDialogMassage = '', 0, 20)
        Rectangle (55,54 350x30), "%s", text variable: RECIPE_CTRL_V2.sStatus.sgShowDialogMassage, invisible if: RECIPE_CTRL_V2.sStatus.sgShowDialogMassage = ''
        Button (73,109 125x65), "确定", text list: 'TextList_Recipe', text index: 120
            p55702900: SEL(RECIPE_CTRL_V2.sCmd.bRecipeConfirmYes, 16#000000, 16#00FF00)
            tap RECIPE_CTRL_V2.sCmd.bRecipeConfirmYes
        Button (263,109 125x65), "取消", text list: 'TextList_Recipe', text index: 121
            p55702900: SEL(RECIPE_CTRL_V2.sCmd.bRecipeConfirmNo, 16#000000, 16#00FF00)
            tap RECIPE_CTRL_V2.sCmd.bRecipeConfirmNo
END_VISUALIZATION

// ---- Visualizations/9_FBs & FCs/Files Operation/Recipe/PH/V2/Files Name/PH_RECIPE_CURRENT_OPEN_FILE_2.TcVIS
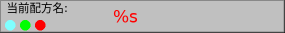
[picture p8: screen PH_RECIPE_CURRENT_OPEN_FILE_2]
VISUALIZATION PH_RECIPE_CURRENT_OPEN_FILE_2  // 285x33
VAR_INPUT
	RECIPE_CTRL_V2 : ST_RecipeCtrl_2;
END_VAR
VAR_INPUT
	Right_Edge_Rel : UDINT;
END_VAR
    Rectangle (0,0 285x33), "当前配方名:", text list: 'TextList_Recipe', text index: 101
        p874137650: Right_Edge_Rel
    Rectangle (110,0 175x33), "%s", text variable: RECIPE_CTRL_V2.sStatus.sgCurUsedFileDisplay
        p874137650: Right_Edge_Rel
    Ellipse (5,20 10x10), colour toggle: (RECIPE_CTRL_V2.sStatus.bFlashLamp) <> 0, invisible if: NOT RECIPE_CTRL_V2.sStatus.bBusy
    Ellipse (20,20 10x10), invisible if: NOT RECIPE_CTRL_V2.sStatus.bDone
    Ellipse (35,20 10x10), invisible if: NOT RECIPE_CTRL_V2.sStatus.bError
END_VISUALIZATION

// ---- Visualizations/9_FBs & FCs/Files Operation/Recipe/PH/V2/Files Name/PH_RECIPE_FILE_PATH_2.TcVIS
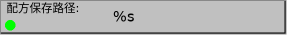
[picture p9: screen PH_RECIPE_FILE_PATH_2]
VISUALIZATION PH_RECIPE_FILE_PATH_2  // 287x35
VAR_INPUT
	RECIPE_CTRL_V2 : ST_RecipeCtrl_2;
END_VAR
VAR_INPUT
	Right_Edge_Rel : UDINT;
END_VAR
    Rectangle (0,0 285x33), "配方保存路径:", input disabled if: TRUE, text list: 'TextList_Recipe', text index: 100
        p874137650: Right_Edge_Rel
    Rectangle (110,0 175x33), "%s", text variable: RECIPE_CTRL_V2.sStatus.sgFilePath
        p874137650: Right_Edge_Rel
    Ellipse (5,20 10x10), invisible if: NOT RECIPE_CTRL_V2.sStatus.bInitialOk
END_VISUALIZATION

// ---- Visualizations/9_FBs & FCs/Files Operation/Recipe/PH/V2/Files Name/PH_RECIPE_LOAD_FILE_NAME_2.TcVIS
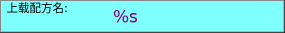
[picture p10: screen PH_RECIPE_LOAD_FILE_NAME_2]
VISUALIZATION PH_RECIPE_LOAD_FILE_NAME_2  // 285x33
VAR_IN_OUT
	RECIPE_CTRL_V2 : ST_RecipeCtrl_2;
END_VAR
VAR_INPUT
	Right_Edge_Rel : UDINT;
END_VAR
    Rectangle (0,0 285x33), "上载配方名:", input disabled if: true, text list: 'TextList_Recipe', text index: 103
        p874137650: Right_Edge_Rel
    Rectangle (110,0 175x33), "%s", text variable: RECIPE_CTRL_V2.sgFileNameLoad
        p874137650: Right_Edge_Rel
        OnMouseClick: write the text variable via Edit
END_VISUALIZATION

// ---- Visualizations/9_FBs & FCs/Files Operation/Recipe/PH/V2/Files Name/PH_RECIPE_SAVE_FILE_NAME_2.TcVIS
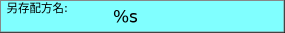
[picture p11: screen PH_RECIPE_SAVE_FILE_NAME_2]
VISUALIZATION PH_RECIPE_SAVE_FILE_NAME_2  // 285x33
VAR_IN_OUT
	RECIPE_CTRL_V2 : ST_RecipeCtrl_2;
END_VAR
VAR_INPUT
	Right_Edge_Rel : UDINT;
END_VAR
    Rectangle (0,0 285x33), "另存配方名:", input disabled if: true, text list: 'TextList_Recipe', text index: 102
        p874137650: Right_Edge_Rel
    Rectangle (110,0 175x33), "%s", text variable: RECIPE_CTRL_V2.sgFileNameSave
        p874137650: Right_Edge_Rel
        OnMouseClick: write the text variable via Edit
END_VISUALIZATION

// ---- Visualizations/9_FBs & FCs/Files Operation/Recipe/PH/V2/Recipe Name/PH_RECIPE_FILE_NAME_DISPLAY_1.TcVIS
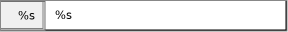
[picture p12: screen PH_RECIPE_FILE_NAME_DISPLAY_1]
VISUALIZATION PH_RECIPE_FILE_NAME_DISPLAY_1  // 288x32
VAR_IN_OUT
	RECIPE_CTRL_V2 : ST_RecipeCtrl_2;
END_VAR
VAR_INPUT
	IDX : UDINT;
END_VAR
VAR_INPUT
	Right_Edge_Rel : INT;
END_VAR
    Rectangle (0,0 286x30), input disabled if: TRUE, colour variable: RECIPE_CTRL_V2.sStatus.asFileDisplay[IDX].b32FillColor
        p874137650: Right_Edge_Rel
    Rectangle (45,1 238x28), "%s", text variable: RECIPE_CTRL_V2.sStatus.asFileDisplay[IDX].sgFilesName, input disabled if: RECIPE_CTRL_V2.sStatus.asFileDisplay[IDX].sgFilesName = '' OR RECIPE_CTRL_V2.sStatus.bBusy
        p874137650: Right_Edge_Rel
        p55702900: RECIPE_CTRL_V2.sStatus.asFileDisplay[IDX].b32TextColor
        tap RECIPE_CTRL_V2.sStatus.asFileDisplay[IDX].bSelect
    Button (0,1 45x29), "%s", text variable: RECIPE_CTRL_V2.sStatus.asFileDisplay[IDX].u32Index, input disabled if: TRUE
        p55702900: RECIPE_CTRL_V2.sStatus.asFileDisplay[IDX].b32TextColor
END_VISUALIZATION

// ---- Visualizations/9_FBs & FCs/Files Operation/Recipe/PH/V2/Recipe Name/PH_RECIPE_FILE_NAME_DISPLAY_2.TcVIS
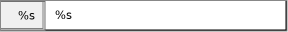
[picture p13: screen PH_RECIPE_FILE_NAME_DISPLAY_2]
VISUALIZATION PH_RECIPE_FILE_NAME_DISPLAY_2  // 288x32
VAR_IN_OUT
	RECIPE_CTRL_V2 : ST_RecipeCtrl_2;
END_VAR
VAR_INPUT
	IDX : UDINT;
END_VAR
VAR_INPUT
	Right_Edge_Rel : INT;
END_VAR
    Rectangle (0,0 286x30), input disabled if: TRUE, colour variable: RECIPE_CTRL_V2.sStatus.asFileDisplay[IDX].b32FillColor
        p874137650: Right_Edge_Rel
    Rectangle (45,1 238x28), "%s", text variable: RECIPE_CTRL_V2.sStatus.asFileDisplay[IDX].sgFilesName, input disabled if: RECIPE_CTRL_V2.sStatus.asFileDisplay[IDX].sgFilesName = '' OR RECIPE_CTRL_V2.sStatus.bBusy
        p874137650: Right_Edge_Rel
        p55702900: RECIPE_CTRL_V2.sStatus.asFileDisplay[IDX].b32TextColor
        OnMouseUp: execute { RECIPE_CTRL_V2.u32RecipeNum:=(RECIPE_CTRL_V2.sStatus.asFileDisplay[IDX].u32Index); }
    Button (0,1 45x29), "%s", text variable: RECIPE_CTRL_V2.sStatus.asFileDisplay[IDX].u32Index, input disabled if: TRUE
        p55702900: RECIPE_CTRL_V2.sStatus.asFileDisplay[IDX].b32TextColor
END_VISUALIZATION

// ---- Visualizations/9_FBs & FCs/Files Operation/Recipe/PH/V2/Scroll/PH_RECIPE_PAGE_BOTTON_2.TcVIS
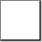
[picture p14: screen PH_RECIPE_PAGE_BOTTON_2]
VISUALIZATION PH_RECIPE_PAGE_BOTTON_2  // 42x42
VAR_IN_OUT
	RECIPE_CTRL_V2 : None;
END_VAR
    Rectangle (0,0 40x40)
        tap RECIPE_CTRL_V2.sCmd.bJumpBottom
    Polyline (35,30), colour toggle: (RECIPE_CTRL_V2.sCmd.bJumpBottom) <> 0
        tap RECIPE_CTRL_V2.sCmd.bJumpBottom
    Polygon (20,20), colour toggle: (RECIPE_CTRL_V2.sCmd.bJumpBottom) <> 0
        tap RECIPE_CTRL_V2.sCmd.bJumpBottom
    Polygon (20,30), colour toggle: (RECIPE_CTRL_V2.sCmd.bJumpBottom) <> 0
        tap RECIPE_CTRL_V2.sCmd.bJumpBottom
END_VISUALIZATION

// ---- Visualizations/9_FBs & FCs/Files Operation/Recipe/PH/V2/Scroll/PH_RECIPE_PAGE_DOWN_2.TcVIS
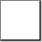
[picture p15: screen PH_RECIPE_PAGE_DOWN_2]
VISUALIZATION PH_RECIPE_PAGE_DOWN_2  // 42x42
VAR_IN_OUT
	RECIPE_CTRL_V2 : None;
END_VAR
    Rectangle (0,0 40x40)
        tap RECIPE_CTRL_V2.sCmd.bPageDown
    Polygon (20,20), colour toggle: (RECIPE_CTRL_V2.sCmd.bPageDown) <> 0
        tap RECIPE_CTRL_V2.sCmd.bPageDown
    Polygon (20,30), colour toggle: (RECIPE_CTRL_V2.sCmd.bPageDown) <> 0
        tap RECIPE_CTRL_V2.sCmd.bPageDown
END_VISUALIZATION

// ---- Visualizations/9_FBs & FCs/Files Operation/Recipe/PH/V2/Scroll/PH_RECIPE_PAGE_TOP_2.TcVIS
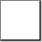
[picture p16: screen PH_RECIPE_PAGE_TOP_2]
VISUALIZATION PH_RECIPE_PAGE_TOP_2  // 42x42
VAR_IN_OUT
	RECIPE_CTRL_V2 : None;
END_VAR
    Rectangle (0,0 40x40)
        tap RECIPE_CTRL_V2.sCmd.bJumpTop
    Polyline (35,10), colour toggle: (RECIPE_CTRL_V2.sCmd.bJumpTop) <> 0
        tap RECIPE_CTRL_V2.sCmd.bJumpTop
    Polygon (20,20), colour toggle: (RECIPE_CTRL_V2.sCmd.bJumpTop) <> 0
        tap RECIPE_CTRL_V2.sCmd.bJumpTop
    Polygon (20,10), colour toggle: (RECIPE_CTRL_V2.sCmd.bJumpTop) <> 0
        tap RECIPE_CTRL_V2.sCmd.bJumpTop
END_VISUALIZATION

// ---- Visualizations/9_FBs & FCs/Files Operation/Recipe/PH/V2/Scroll/PH_RECIPE_PAGE_UP_2.TcVIS
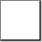
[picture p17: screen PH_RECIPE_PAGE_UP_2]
VISUALIZATION PH_RECIPE_PAGE_UP_2  // 42x42
VAR_IN_OUT
	RECIPE_CTRL_V2 : None;
END_VAR
    Rectangle (0,0 40x40)
        tap RECIPE_CTRL_V2.sCmd.bPageUp
    Polygon (20,20), colour toggle: (RECIPE_CTRL_V2.sCmd.bPageUp) <> 0
        tap RECIPE_CTRL_V2.sCmd.bPageUp
    Polygon (20,10), colour toggle: (RECIPE_CTRL_V2.sCmd.bPageUp) <> 0
        tap RECIPE_CTRL_V2.sCmd.bPageUp
END_VISUALIZATION

// ---- Visualizations/9_FBs & FCs/Files Operation/Recipe/PH/V2/Scroll/PH_RECIPE_REGULAR.TcVIS
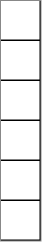
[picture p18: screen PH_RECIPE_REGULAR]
VISUALIZATION PH_RECIPE_REGULAR  // 42x242
VAR_IN_OUT
	RECIPE_CTRL_V2 : ST_RecipeCtrl_2;
END_VAR
    Rectangle (0,40 40x40)
        tap RECIPE_CTRL_V2.sCmd.bPageUp
    Polygon (20,60), colour toggle: (RECIPE_CTRL_V2.sCmd.bPageUp) <> 0
        tap RECIPE_CTRL_V2.sCmd.bPageUp
    Polygon (20,50), colour toggle: (RECIPE_CTRL_V2.sCmd.bPageUp) <> 0
        tap RECIPE_CTRL_V2.sCmd.bPageUp
    Rectangle (0,0 40x40)
        tap RECIPE_CTRL_V2.sCmd.bJumpTop
    Polyline (35,10), colour toggle: (RECIPE_CTRL_V2.sCmd.bJumpTop) <> 0
        tap RECIPE_CTRL_V2.sCmd.bJumpTop
    Polygon (20,20), colour toggle: (RECIPE_CTRL_V2.sCmd.bJumpTop) <> 0
        tap RECIPE_CTRL_V2.sCmd.bJumpTop
    Polygon (20,10), colour toggle: (RECIPE_CTRL_V2.sCmd.bJumpTop) <> 0
        tap RECIPE_CTRL_V2.sCmd.bJumpTop
    Rectangle (0,80 40x40)
        tap RECIPE_CTRL_V2.sCmd.bScrollUp
    Polygon (20,90), colour toggle: (RECIPE_CTRL_V2.sCmd.bScrollUp) <> 0
        tap RECIPE_CTRL_V2.sCmd.bScrollUp
    Rectangle (0,120 40x40)
        p2738717112: RECIPE_CTRL_V2.sStatus.i16RegularOffset
        tap RECIPE_CTRL_V2.sCmd.bScrollDown
    Polygon (20,150), colour toggle: (RECIPE_CTRL_V2.sCmd.bScrollDown) <> 0
        p2738717112: RECIPE_CTRL_V2.sStatus.i16RegularOffset
        tap RECIPE_CTRL_V2.sCmd.bScrollDown
    Rectangle (0,160 40x40)
        p2738717112: RECIPE_CTRL_V2.sStatus.i16RegularOffset
        tap RECIPE_CTRL_V2.sCmd.bPageDown
    Polygon (20,180), colour toggle: (RECIPE_CTRL_V2.sCmd.bPageDown) <> 0
        p2738717112: RECIPE_CTRL_V2.sStatus.i16RegularOffset
        tap RECIPE_CTRL_V2.sCmd.bPageDown
    Polygon (20,190), colour toggle: (RECIPE_CTRL_V2.sCmd.bPageDown) <> 0
        p2738717112: RECIPE_CTRL_V2.sStatus.i16RegularOffset
        tap RECIPE_CTRL_V2.sCmd.bPageDown
    Rectangle (0,200 40x40)
        p2738717112: RECIPE_CTRL_V2.sStatus.i16RegularOffset
        tap RECIPE_CTRL_V2.sCmd.bJumpBottom
    Polyline (35,230), colour toggle: (RECIPE_CTRL_V2.sCmd.bJumpBottom) <> 0
        p2738717112: RECIPE_CTRL_V2.sStatus.i16RegularOffset
        tap RECIPE_CTRL_V2.sCmd.bJumpBottom
    Polygon (20,220), colour toggle: (RECIPE_CTRL_V2.sCmd.bJumpBottom) <> 0
        p2738717112: RECIPE_CTRL_V2.sStatus.i16RegularOffset
        tap RECIPE_CTRL_V2.sCmd.bJumpBottom
    Polygon (20,230), colour toggle: (RECIPE_CTRL_V2.sCmd.bJumpBottom) <> 0
        p2738717112: RECIPE_CTRL_V2.sStatus.i16RegularOffset
        tap RECIPE_CTRL_V2.sCmd.bJumpBottom
    Rectangle (0,120 40x0)
        p1126004900: RECIPE_CTRL_V2.sStatus.i16RegularOffset
END_VISUALIZATION

// ---- Visualizations/9_FBs & FCs/Files Operation/Recipe/PH/V2/Scroll/PH_RECIPE_REGULAR_1.TcVIS
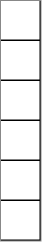
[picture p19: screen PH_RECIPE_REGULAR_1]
VISUALIZATION PH_RECIPE_REGULAR_1  // 42x242
VAR_IN_OUT
	RECIPE_CTRL_V2 : ST_RecipeCtrl_2;
END_VAR
    Frame (0,0 40x40)
        shows PH_RECIPE_PAGE_TOP_2(RECIPE_CTRL_V2 := RECIPE_CTRL_V2)
        pReferences[0]: m_Input_RECIPE_CTRL_V2=m_Input_RECIPE_CTRL_V2
    Frame (0,40 40x40)
        shows PH_RECIPE_PAGE_UP_2(RECIPE_CTRL_V2 := RECIPE_CTRL_V2)
        pReferences[0]: m_Input_RECIPE_CTRL_V2=m_Input_RECIPE_CTRL_V2
    Frame (0,80 40x40)
        shows PH_RECIPE_SCROLL_UP_2(RECIPE_CTRL_V2 := RECIPE_CTRL_V2)
        pReferences[0]: m_Input_RECIPE_CTRL_V2=m_Input_RECIPE_CTRL_V2
    Frame (0,120 40x40)
        shows PH_RECIPE_SCROLL_DOWN_2(RECIPE_CTRL_V2 := RECIPE_CTRL_V2)
        pReferences[0]: m_Input_RECIPE_CTRL_V2=m_Input_RECIPE_CTRL_V2
        p2738717112: RECIPE_CTRL_V2.sStatus.i16RegularOffset
    Rectangle (0,40 40x40)
        tap RECIPE_CTRL_V2.sCmd.bPageUp
    Polygon (20,60), colour toggle: (RECIPE_CTRL_V2.sCmd.bPageUp) <> 0
        tap RECIPE_CTRL_V2.sCmd.bPageUp
    Polygon (20,50), colour toggle: (RECIPE_CTRL_V2.sCmd.bPageUp) <> 0
        tap RECIPE_CTRL_V2.sCmd.bPageUp
    Rectangle (0,0 40x40)
        tap RECIPE_CTRL_V2.sCmd.bJumpTop
    Polyline (35,10), colour toggle: (RECIPE_CTRL_V2.sCmd.bJumpTop) <> 0
        tap RECIPE_CTRL_V2.sCmd.bJumpTop
    Polygon (20,20), colour toggle: (RECIPE_CTRL_V2.sCmd.bJumpTop) <> 0
        tap RECIPE_CTRL_V2.sCmd.bJumpTop
    Polygon (20,10), colour toggle: (RECIPE_CTRL_V2.sCmd.bJumpTop) <> 0
        tap RECIPE_CTRL_V2.sCmd.bJumpTop
    Rectangle (0,80 40x40)
        tap RECIPE_CTRL_V2.sCmd.bScrollUp
    Polygon (20,90), colour toggle: (RECIPE_CTRL_V2.sCmd.bScrollUp) <> 0
        tap RECIPE_CTRL_V2.sCmd.bScrollUp
    Rectangle (0,120 40x40)
        p2738717112: RECIPE_CTRL_V2.sStatus.i16RegularOffset
        tap RECIPE_CTRL_V2.sCmd.bScrollDown
    Polygon (20,150), colour toggle: (RECIPE_CTRL_V2.sCmd.bScrollDown) <> 0
        p2738717112: RECIPE_CTRL_V2.sStatus.i16RegularOffset
        tap RECIPE_CTRL_V2.sCmd.bScrollDown
    Rectangle (0,160 40x40)
        p2738717112: RECIPE_CTRL_V2.sStatus.i16RegularOffset
        tap RECIPE_CTRL_V2.sCmd.bPageDown
    Polygon (20,180), colour toggle: (RECIPE_CTRL_V2.sCmd.bPageDown) <> 0
        p2738717112: RECIPE_CTRL_V2.sStatus.i16RegularOffset
        tap RECIPE_CTRL_V2.sCmd.bPageDown
    Polygon (20,190), colour toggle: (RECIPE_CTRL_V2.sCmd.bPageDown) <> 0
        p2738717112: RECIPE_CTRL_V2.sStatus.i16RegularOffset
        tap RECIPE_CTRL_V2.sCmd.bPageDown
    Rectangle (0,200 40x40)
        p2738717112: RECIPE_CTRL_V2.sStatus.i16RegularOffset
        tap RECIPE_CTRL_V2.sCmd.bJumpBottom
    Polyline (35,230), colour toggle: (RECIPE_CTRL_V2.sCmd.bJumpBottom) <> 0
        p2738717112: RECIPE_CTRL_V2.sStatus.i16RegularOffset
        tap RECIPE_CTRL_V2.sCmd.bJumpBottom
    Polygon (20,220), colour toggle: (RECIPE_CTRL_V2.sCmd.bJumpBottom) <> 0
        p2738717112: RECIPE_CTRL_V2.sStatus.i16RegularOffset
        tap RECIPE_CTRL_V2.sCmd.bJumpBottom
    Polygon (20,230), colour toggle: (RECIPE_CTRL_V2.sCmd.bJumpBottom) <> 0
        p2738717112: RECIPE_CTRL_V2.sStatus.i16RegularOffset
        tap RECIPE_CTRL_V2.sCmd.bJumpBottom
    Rectangle (0,120 40x0)
        p1126004900: RECIPE_CTRL_V2.sStatus.i16RegularOffset
END_VISUALIZATION

// ---- Visualizations/9_FBs & FCs/Files Operation/Recipe/PH/V2/Scroll/PH_RECIPE_SCROLL_DOWN_2.TcVIS
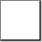
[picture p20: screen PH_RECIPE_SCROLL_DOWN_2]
VISUALIZATION PH_RECIPE_SCROLL_DOWN_2  // 42x42
VAR_IN_OUT
	RECIPE_CTRL_V2 : None;
END_VAR
    Rectangle (0,0 40x40)
        tap RECIPE_CTRL_V2.sCmd.bScrollDown
    Polygon (20,30), colour toggle: (RECIPE_CTRL_V2.sCmd.bScrollDown) <> 0
        tap RECIPE_CTRL_V2.sCmd.bScrollDown
END_VISUALIZATION

// ---- Visualizations/9_FBs & FCs/Files Operation/Recipe/PH/V2/Scroll/PH_RECIPE_SCROLL_UP_2.TcVIS
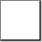
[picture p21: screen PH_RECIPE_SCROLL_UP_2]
VISUALIZATION PH_RECIPE_SCROLL_UP_2  // 42x42
VAR_IN_OUT
	RECIPE_CTRL_V2 : None;
END_VAR
    Rectangle (0,0 40x40)
        tap RECIPE_CTRL_V2.sCmd.bScrollUp
    Polygon (20,10), colour toggle: (RECIPE_CTRL_V2.sCmd.bScrollUp) <> 0
        tap RECIPE_CTRL_V2.sCmd.bScrollUp
END_VISUALIZATION

// ---- Visualizations/9_FBs & FCs/Files Operation/Recipe/question.TcTLO
TEXTLIST question
  1 = '确定要删除当前配方文件吗?' | chinese: '确定要删除当前配方文件吗?' | english: 'Are you sure you want to delete current recipe file?'
  2 = '确认要上载并激活当前配方文件吗?' | chinese: '确认要上载并激活当前配方文件吗?' | english: 'Are you sure you want to upload and active current recipe file?'
  3 = '确认要替换当前配方文件吗(已有同名配方)?' | chinese: '确认要替换当前配方文件吗(已有同名配方)?' | english: 'Are you sure you want to replace current recipe file?'
  10 = '确认要从USB中导入配方文件吗?' | chinese: '确认要从USB中导入配方文件吗?' | english: 'Are you sure you want to import recipe file from USB device?'
  11 = '确认要复制并替换掉目标文件夹的同名文件吗?' | chinese: '确认要复制并替换掉目标文件夹的同名文件吗?' | english: 'Are you sure you want to copy and replace the file in the dest folder?'
  12 = '' | english: '12'
  20 = '确认要把文件导出到USB中吗?' | chinese: '确认要把文件导出到USB中吗?' | english: 'Are you sure you want to export recipe file to USB device?'
  21 = '确认要复制并替换掉目标文件夹的同名文件吗?' | chinese: '确认要复制并替换掉目标文件夹的同名文件吗?' | english: 'Are you sure you want to copy and replace the file in the dest folder?'
  22 = '' | english: '22'
  30 = '没有发现USB设备' | chinese: '没有发现USB设备' | english: 'No USB device.'
   = ''
END_TEXTLIST

// ---- Visualizations/9_FBs & FCs/Files Operation/Recipe/SystemDisplay.TcTLO
TEXTLIST SystemDisplay
  1 = 'Window XP' | chinese: 'Window XP' | english: 'Window XP'
  2 = 'U盘' | chinese: 'U盘' | english: 'USB Device'
  3 = 'Window CE' | chinese: 'Window CE' | english: 'Window CE'
   = ''
END_TEXTLIST

// ---- Visualizations/9_FBs & FCs/Files Operation/Recipe/TextList_Recipe.TcTLO
TEXTLIST TextList_Recipe
  100 = ' 配方保存路径:' | chinese: ' 配方保存路径:' | english: ' Recipe Save Path:'
  101 = ' 当前配方名:' | chinese: ' 当前配方名:' | english: ' Current Recipe:'
  102 = ' 另存配方名:' | chinese: ' 另存配方名:' | english: ' Save as Recipe:'
  103 = ' 上载配方名:' | chinese: ' 上载配方名:' | english: ' Upload Recipe:'
  110 = '刷新' | chinese: '刷新' | english: 'FlashList'
  111 = '上载并激活' | chinese: '上载并激活' | english: 'LoadRecipe'
  112 = '保存' | chinese: '保存' | english: 'SaveRecipe'
  113 = '另存为...' | chinese: '另存为...' | english: 'SaveRecipeAs'
  114 = '删除' | chinese: '删除' | english: 'DeleteRecipe'
  119 = '从USB导入' | chinese: '从USB导入' | english: 'LoadFromUSB'
  120 = '确定' | chinese: '确定' | english: 'OK'
  121 = '取消' | chinese: '取消' | english: 'Cancel'
  118 = '导出到USB' | chinese: '导出到USB' | english: 'SaveToUSB'
   = ''
END_TEXTLIST

// ---- Visualizations/9_FBs & FCs/Payment/PH_PAYMENT_CTRL.TcVIS
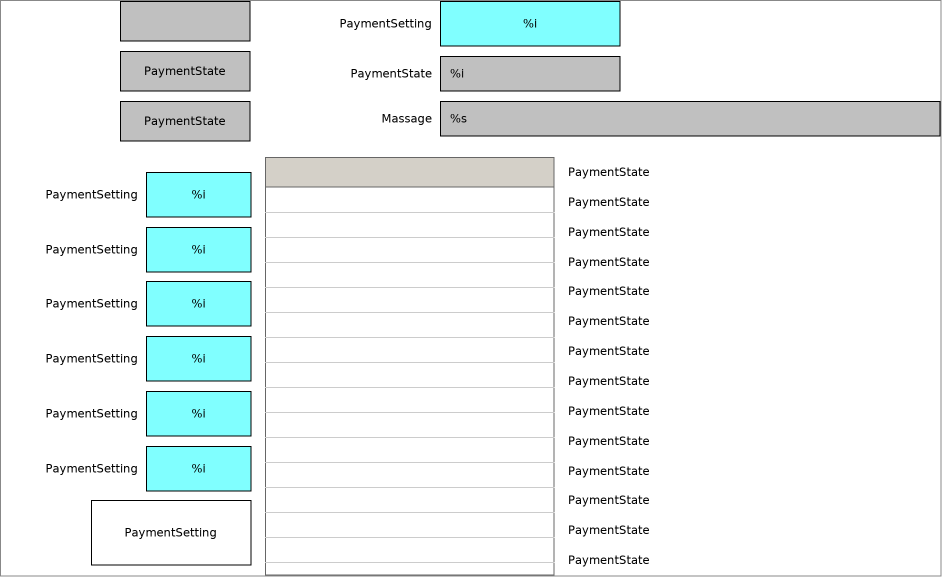
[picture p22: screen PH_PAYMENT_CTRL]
VISUALIZATION PH_PAYMENT_CTRL  // 942x577
VAR_IN_OUT
	fbPaymentDetect			: FB_Payment;	//定义FB的路径
	sPaymentSet_HMI			: ST_Payment	//定义ST的路径
	bSettingInvisible		: BOOL;			//设定参数(年, 月, 日, 密码等)隐藏
	bSettingInputDisable	: BOOL;			//设定参数(年, 月, 日, 密码等)禁止输入
END_VAR
    Rectangle (120,51 130x40), "PaymentState", colour toggle: fbPaymentDetect.bPaymentLock, text list: 'TextList_Payment', text index: 103
    Rectangle (120,101 130x40), "PaymentState", colour toggle: fbPaymentDetect.bPaymentAhead, text list: 'TextList_Payment', text index: 102
    Rectangle (120,1 130x40), colour toggle: fbPaymentDetect.bPaymentEnable, text list: 'TextList_Payment', text index: 100 + BOOL_TO_INT(fbPaymentDetect.bPaymentEnable)
    Rectangle (295,101 140x35), "Massage"
    Rectangle (295,1 140x45), "PaymentSetting", text list: 'TextList_Payment', text index: 9
    Rectangle (440,1 180x45), "%i", text variable: sPaymentSet_HMI.nPassword
        OnMouseClick: write the text variable via VisuDialogs.Numpad
    Rectangle (295,56 140x35), "PaymentState", text list: 'TextList_Payment', text index: 109
    Rectangle (440,56 180x35), "%i", text variable: fbPaymentDetect.nPayLevel
    Rectangle (1,172 140x45), "PaymentSetting", text list: 'TextList_Payment', text index: 1
    Rectangle (1,227 140x45), "PaymentSetting", text list: 'TextList_Payment', text index: 2
    Rectangle (1,281 140x45), "PaymentSetting", text list: 'TextList_Payment', text index: 3
    Rectangle (1,336 140x45), "PaymentSetting", text list: 'TextList_Payment', text index: 4
    Rectangle (1,391 140x45), "PaymentSetting", text list: 'TextList_Payment', text index: 5
    Rectangle (1,446 140x45), "PaymentSetting", text list: 'TextList_Payment', text index: 6
    Group (91,157 833x418), invisible if: bSettingInvisible, input disabled if: bSettingInputDisable
        Rectangle (0,343 160x65), "PaymentSetting", colour toggle: sPaymentSet_HMI.bEnable, text list: 'TextList_Payment', text index: 0
            tap sPaymentSet_HMI.bEnable
        Table (174,0 289x418), data array: sPaymentSet_HMI.anPaymentPassword
            p3854506369: sPaymentSet_HMI.anPaymentPassword[INDEX]
            Columns.Column.[0].Template: sPaymentSet_HMI.anPaymentPassword[INDEX] <> 0; OnMouseClick: write the text variable via VisuDialogs.Numpad
        Rectangle (55,15 105x45), "%i", text variable: sPaymentSet_HMI.wYear, colour toggle: fbPaymentDetect.bPaymentEnable, input disabled if: fbPaymentDetect.bPaymentEnable
            OnMouseClick: write the text variable via VisuDialogs.Numpad
        Rectangle (55,70 105x45), "%i", text variable: sPaymentSet_HMI.wMonth, colour toggle: fbPaymentDetect.bPaymentEnable, input disabled if: fbPaymentDetect.bPaymentEnable
            OnMouseClick: write the text variable via VisuDialogs.Numpad
        Rectangle (55,124 105x45), "%i", text variable: sPaymentSet_HMI.wDay, colour toggle: fbPaymentDetect.bPaymentEnable, input disabled if: fbPaymentDetect.bPaymentEnable
            OnMouseClick: write the text variable via VisuDialogs.Numpad
        Rectangle (55,179 105x45), "%i", text variable: sPaymentSet_HMI.iPaymentNo, colour toggle: fbPaymentDetect.bPaymentEnable, input disabled if: fbPaymentDetect.bPaymentEnable
            OnMouseClick: write the text variable via VisuDialogs.Numpad
        Rectangle (55,234 105x45), "%i", text variable: sPaymentSet_HMI.iMonth, colour toggle: fbPaymentDetect.bPaymentEnable, input disabled if: fbPaymentDetect.bPaymentEnable
            OnMouseClick: write the text variable via VisuDialogs.Numpad
        Rectangle (55,289 105x45), "%i", text variable: sPaymentSet_HMI.iAheadDays, colour toggle: fbPaymentDetect.bPaymentEnable, input disabled if: fbPaymentDetect.bPaymentEnable
            OnMouseClick: write the text variable via VisuDialogs.Numpad
        Rectangle (474,0 359x30), "PaymentState", text list: 'TextList_Payment', text index: 110
        Rectangle (474,30 359x30), "PaymentState", text list: 'TextList_Payment', text index: 111
        Rectangle (474,60 359x30), "PaymentState", text list: 'TextList_Payment', text index: 112
        Rectangle (474,90 359x30), "PaymentState", text list: 'TextList_Payment', text index: 113
        Rectangle (474,119 359x30), "PaymentState", text list: 'TextList_Payment', text index: 114
        Rectangle (474,149 359x30), "PaymentState", text list: 'TextList_Payment', text index: 115
        Rectangle (474,179 359x30), "PaymentState", text list: 'TextList_Payment', text index: 116
        Rectangle (474,209 359x30), "PaymentState", text list: 'TextList_Payment', text index: 117
        Rectangle (474,239 359x30), "PaymentState", text list: 'TextList_Payment', text index: 118
        Rectangle (474,269 359x30), "PaymentState", text list: 'TextList_Payment', text index: 119
        Rectangle (474,299 359x30), "PaymentState", text list: 'TextList_Payment', text index: 120
        Rectangle (474,328 359x30), "PaymentState", text list: 'TextList_Payment', text index: 121
        Rectangle (474,358 359x30), "PaymentState", text list: 'TextList_Payment', text index: 122
        Rectangle (474,388 359x30), "PaymentState", text list: 'TextList_Payment', text index: 123
    Rectangle (440,101 500x35), "%s", text variable: sPaymentSet_HMI.sgMassage
END_VISUALIZATION

// ---- Visualizations/9_FBs & FCs/Payment/TextList_Payment.TcTLO
TEXTLIST TextList_Payment
  0 = '激活' | chinese: '激活' | english: 'Active'
  1 = '开始时间--年' | chinese: '开始时间--年' | english: 'Year'
  2 = '开始时间--月' | chinese: '开始时间--月' | english: 'Month'
  3 = '开始时间--日' | chinese: '开始时间--日' | english: 'Day'
  4 = '分期期数' | chinese: '分期期数' | english: 'Payment Time'
  5 = '两期间隔月数' | chinese: '两期间隔月数' | english: 'Interval Month'
  6 = '提前通知天数' | chinese: '提前通知天数' | english: 'Ahead Days'
  9 = '请输入解锁密码' | chinese: '请输入解锁密码' | english: 'Unlock Password'
  10 = '设定' | chinese: '设定' | english: 'Setting'
  11 = '实际' | chinese: '实际' | english: 'Actual'
  100 = '禁用' | chinese: '禁用' | english: 'Disable'
  101 = '启用' | chinese: '启用' | english: 'Enable'
  102 = '提示将要锁机' | chinese: '提示将要锁机' | english: '提示将要锁机'
  103 = '锁机报警' | chinese: '锁机报警' | english: '锁机报警'
  109 = '当前期数' | chinese: '当前期数' | english: '当前期数'
  110 = '说明:' | chinese: '说明:' | english: '说明:'
  111 = '1. 先输入开始计算分期的日期密码等，' | chinese: '1. 先输入开始计算分期的日期密码等，' | english: '1. 先输入开始计算分期的日期密码等，'
  112 = '   然后点击“激活”按钮，开始计时。' | chinese: '   然后点击“激活”按钮，开始计时。' | english: '   然后点击“激活”按钮，开始计时。'
  113 = '2. 激活后，上方的状态切换为“启用”，' | chinese: '2. 激活后，上方的状态切换为“启用”，' | english: '2. 激活后，上方的状态切换为“启用”，'
  114 = '   并显示当前已经到第几期密码。启用' | chinese: '   并显示当前已经到第几期密码。启用' | english: '   并显示当前已经到第几期密码。启用'
  115 = '   后，不能再修改开始日期，如果要修' | chinese: '   后，不能再修改开始日期，如果要修' | english: '   后，不能再修改开始日期，如果要修'
  116 = '   改，只能是输入最后一期密码解锁后，' | chinese: '   改，只能是输入最后一期密码解锁后，' | english: '   改，只能是输入最后一期密码解锁后，'
  117 = '   重新激活。启用后，可以修改各期密\t' | chinese: '   重新激活。启用后，可以修改各期密\t' | english: '   重新激活。启用后，可以修改各期密\t'
  118 = '   码，修改后再按下“激活”按钮生效。' | chinese: '   码，修改后再按下“激活”按钮生效。' | english: '   码，修改后再按下“激活”按钮生效。'
  119 = '3. 密码不能设置成一样，否则只是最低等' | chinese: '3. 密码不能设置成一样，否则只是最低等' | english: '3. 密码不能设置成一样，否则只是最低等'
  120 = '   级的有效，密码不能设置成"9999999"' | chinese: '   级的有效，密码不能设置成"9999999"' | english: '   级的有效，密码不能设置成"9999999"'
  121 = ''
  122 = ''
  123 = ''
  124 = ''
  125 = ''
   = ''
END_TEXTLIST

// ---- Visualizations/Demo_Recipe_HMI/BECKHOFF_PLC_HMI.TcVIS
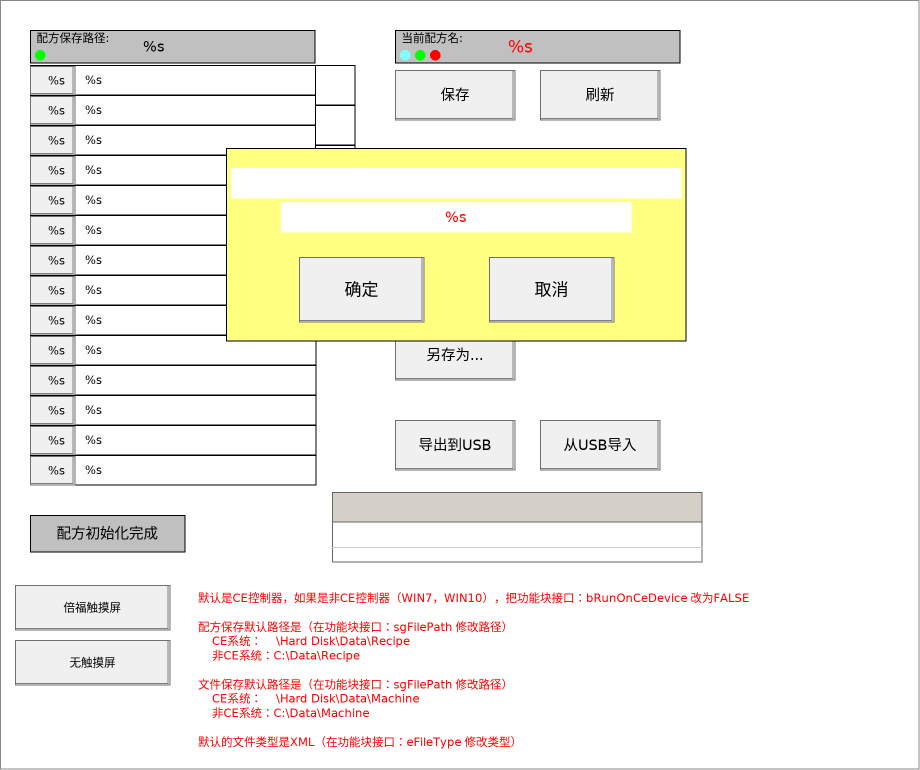
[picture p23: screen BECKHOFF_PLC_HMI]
VISUALIZATION BECKHOFF_PLC_HMI  // 920x770
    RoundedRectangle (30,515 155x37), "配方初始化完成", colour toggle: (Recipe_Manager.g_sRecipeCtrl.sStatus.bInitialOk) <> 0
    Button (15,585 155x45), "倍福触摸屏"
        OnMouseClick: execute { P099_Call_Recipe.iHMI := 1; }
    Rectangle (195,590 725x180), "默认是CE控制器，如果是非CE控制器（WIN7，WIN10），把功能块接口：bRunOnCeDevice 改为FALSE 配方保存默认路径是（在功能块接口：sgFilePath 修改路径） CE系统： \Hard Disk\Data\Recipe 非CE系统：C:\Data\Recipe 文件保存默认路径是（在功能块接口：sgFilePath 修改路径） CE系统： \Hard Disk\Data\Machine 非CE系统：C:\Data\Machine 默认的文件类型是XML（在功能块接口：eFileType 修改类型）"
    Frame (395,195 110x50)
        shows PH_RECIPE_BUTTON_LOAD_2(RECIPE_CTRL_V2 := Recipe_Manager.g_sRecipeCtrl)
        pReferences[0]: m_Input_RECIPE_CTRL_V2=Global_Variables_forRecipe.g_sRecipeCtrl
    Frame (395,330 110x50)
        shows PH_RECIPE_BUTTON_SAVE_AS_2(RECIPE_CTRL_V2 := Recipe_Manager.g_sRecipeCtrl)
        pReferences[0]: m_Input_RECIPE_CTRL_V2=Global_Variables_forRecipe.g_sRecipeCtrl
    Frame (395,70 110x50)
        shows PH_RECIPE_BUTTON_SAVE_2(RECIPE_CTRL_V2 := Recipe_Manager.g_sRecipeCtrl)
        pReferences[0]: m_Input_RECIPE_CTRL_V2=Global_Variables_forRecipe.g_sRecipeCtrl
    Frame (540,70 110x50)
        shows PH_RECIPE_BUTTON_FLASH_2(RECIPE_CTRL_V2 := Recipe_Manager.g_sRecipeCtrl)
        pReferences[0]: m_Input_RECIPE_CTRL_V2=Global_Variables_forRecipe.g_sRecipeCtrl
    Frame (540,195 110x50)
        shows PH_RECIPE_BUTTON_DELETE_2(RECIPE_CTRL_V2 := Recipe_Manager.g_sRecipeCtrl)
        pReferences[0]: m_Input_RECIPE_CTRL_V2=Global_Variables_forRecipe.g_sRecipeCtrl
    Frame (395,420 110x50)
        shows PH_RECIPE_BUTTON_TO_USB_2(RECIPE_CTRL_V2 := Recipe_Manager.g_sRecipeCtrl)
        pReferences[0]: m_Input_RECIPE_CTRL_V2=Global_Variables_forRecipe.g_sRecipeCtrl
    Frame (540,420 110x50)
        shows PH_RECIPE_BUTTON_FROM_USB_2(RECIPE_CTRL_V2 := Recipe_Manager.g_sRecipeCtrl)
        pReferences[0]: m_Input_RECIPE_CTRL_V2=Global_Variables_forRecipe.g_sRecipeCtrl
    Frame (30,30 285x35)
        shows PH_RECIPE_FILE_PATH_2(RECIPE_CTRL_V2 := Recipe_Manager.g_sRecipeCtrl, Right_Edge_Rel := 40)
        pReferences[0]: m_Input_RECIPE_CTRL_V2=Global_Variables_forRecipe.g_sRecipeCtrl, m_Input_Right_Edge_Rel=40
    Frame (395,30 285x35)
        shows PH_RECIPE_CURRENT_OPEN_FILE_2(RECIPE_CTRL_V2 := Recipe_Manager.g_sRecipeCtrl, Right_Edge_Rel := 80)
        pReferences[0]: m_Input_RECIPE_CTRL_V2=Global_Variables_forRecipe.g_sRecipeCtrl, m_Input_Right_Edge_Rel=80
    Frame (395,150 285x35)
        shows PH_RECIPE_LOAD_FILE_NAME_2(RECIPE_CTRL_V2 := Recipe_Manager.g_sRecipeCtrl, Right_Edge_Rel := 80)
        pReferences[0]: m_Input_RECIPE_CTRL_V2=Global_Variables_forRecipe.g_sRecipeCtrl, m_Input_Right_Edge_Rel=80
    Frame (395,280 285x35)
        shows PH_RECIPE_SAVE_FILE_NAME_2(RECIPE_CTRL_V2 := Recipe_Manager.g_sRecipeCtrl, Right_Edge_Rel := 80)
        pReferences[0]: m_Input_RECIPE_CTRL_V2=Global_Variables_forRecipe.g_sRecipeCtrl, m_Input_Right_Edge_Rel=80
    Frame (30,65 290x35)
        shows PH_RECIPE_FILE_NAME_DISPLAY_2(RECIPE_CTRL_V2 := Recipe_Manager.g_sRecipeCtrl, IDX := 1, Right_Edge_Rel := 0)
    Frame (30,95 290x35)
        shows PH_RECIPE_FILE_NAME_DISPLAY_2(RECIPE_CTRL_V2 := Recipe_Manager.g_sRecipeCtrl, IDX := 2, Right_Edge_Rel := 0)
        pReferences[0]: m_Input_RECIPE_CTRL_V2=Global_Variables_forRecipe.g_sRecipeCtrl, m_Input_IDX=2
    Frame (30,125 290x35)
        shows PH_RECIPE_FILE_NAME_DISPLAY_2(RECIPE_CTRL_V2 := Recipe_Manager.g_sRecipeCtrl, IDX := 3, Right_Edge_Rel := 0)
        pReferences[0]: m_Input_RECIPE_CTRL_V2=Global_Variables_forRecipe.g_sRecipeCtrl, m_Input_IDX=3
    Frame (30,155 290x35)
        shows PH_RECIPE_FILE_NAME_DISPLAY_2(RECIPE_CTRL_V2 := Recipe_Manager.g_sRecipeCtrl, IDX := 4, Right_Edge_Rel := 0)
        pReferences[0]: m_Input_RECIPE_CTRL_V2=Global_Variables_forRecipe.g_sRecipeCtrl, m_Input_IDX=4
    Frame (30,185 290x35)
        shows PH_RECIPE_FILE_NAME_DISPLAY_2(RECIPE_CTRL_V2 := Recipe_Manager.g_sRecipeCtrl, IDX := 5, Right_Edge_Rel := 0)
        pReferences[0]: m_Input_RECIPE_CTRL_V2=Global_Variables_forRecipe.g_sRecipeCtrl, m_Input_IDX=5
    Frame (30,215 290x35)
        shows PH_RECIPE_FILE_NAME_DISPLAY_2(RECIPE_CTRL_V2 := Recipe_Manager.g_sRecipeCtrl, IDX := 6, Right_Edge_Rel := 0)
        pReferences[0]: m_Input_RECIPE_CTRL_V2=Global_Variables_forRecipe.g_sRecipeCtrl, m_Input_IDX=6
    Frame (30,245 290x35)
        shows PH_RECIPE_FILE_NAME_DISPLAY_2(RECIPE_CTRL_V2 := Recipe_Manager.g_sRecipeCtrl, IDX := 7, Right_Edge_Rel := 0)
        pReferences[0]: m_Input_RECIPE_CTRL_V2=Global_Variables_forRecipe.g_sRecipeCtrl, m_Input_IDX=7
    Frame (30,275 290x35)
        shows PH_RECIPE_FILE_NAME_DISPLAY_2(RECIPE_CTRL_V2 := Recipe_Manager.g_sRecipeCtrl, IDX := 8, Right_Edge_Rel := 0)
        pReferences[0]: m_Input_RECIPE_CTRL_V2=Global_Variables_forRecipe.g_sRecipeCtrl, m_Input_IDX=8
    Frame (30,305 290x35)
        shows PH_RECIPE_FILE_NAME_DISPLAY_2(RECIPE_CTRL_V2 := Recipe_Manager.g_sRecipeCtrl, IDX := 9, Right_Edge_Rel := 0)
        pReferences[0]: m_Input_RECIPE_CTRL_V2=Global_Variables_forRecipe.g_sRecipeCtrl, m_Input_IDX=9
    Frame (30,335 290x35)
        shows PH_RECIPE_FILE_NAME_DISPLAY_2(RECIPE_CTRL_V2 := Recipe_Manager.g_sRecipeCtrl, IDX := 10, Right_Edge_Rel := 0)
        pReferences[0]: m_Input_RECIPE_CTRL_V2=Global_Variables_forRecipe.g_sRecipeCtrl, m_Input_IDX=10
    Frame (315,65 45x245)
        shows PH_RECIPE_REGULAR(RECIPE_CTRL_V2 := Recipe_Manager.g_sRecipeCtrl)
        pReferences[0]: m_Input_RECIPE_CTRL_V2=Global_Variables_forRecipe.g_sRecipeCtrl
    Frame (30,365 290x35)
        shows PH_RECIPE_FILE_NAME_DISPLAY_2(RECIPE_CTRL_V2 := Recipe_Manager.g_sRecipeCtrl, IDX := 11, Right_Edge_Rel := 0)
        pReferences[0]: m_Input_RECIPE_CTRL_V2=Global_Variables_forRecipe.g_sRecipeCtrl, m_Input_IDX=11
    Frame (30,395 290x35)
        shows PH_RECIPE_FILE_NAME_DISPLAY_2(RECIPE_CTRL_V2 := Recipe_Manager.g_sRecipeCtrl, IDX := 12, Right_Edge_Rel := 0)
        pReferences[0]: m_Input_RECIPE_CTRL_V2=Global_Variables_forRecipe.g_sRecipeCtrl, m_Input_IDX=12
    Frame (30,425 290x35)
        shows PH_RECIPE_FILE_NAME_DISPLAY_2(RECIPE_CTRL_V2 := Recipe_Manager.g_sRecipeCtrl, IDX := 13, Right_Edge_Rel := 0)
        pReferences[0]: m_Input_RECIPE_CTRL_V2=Global_Variables_forRecipe.g_sRecipeCtrl, m_Input_IDX=13
    Frame (30,455 290x35)
        shows PH_RECIPE_FILE_NAME_DISPLAY_2(RECIPE_CTRL_V2 := Recipe_Manager.g_sRecipeCtrl, IDX := 14, Right_Edge_Rel := 0)
        pReferences[0]: m_Input_RECIPE_CTRL_V2=Global_Variables_forRecipe.g_sRecipeCtrl, m_Input_IDX=14
    Frame (225,147 350x195)
        shows PH_RECIPE_CONFIRM_WINDOW_2(RECIPE_CTRL_V2 := Recipe_Manager.g_sRecipeCtrl)
        pReferences[0]: m_Input_RECIPE_CTRL_V2=Global_Variables_forRecipe.g_sRecipeCtrl
    Button (15,640 155x45), "无触摸屏"
        OnMouseClick: execute { P099_Call_Recipe.iHMI := 0; }
    Table (332,492 370x70), data array: sRecData
        p2232123230: rTemp
        p2685023577: sRecData.rTemp
        p3854506369: Global_Variables_Param.sRecData.rTemp
        p511219082: rSpeedRpm
        p3312258591: sRecData.rSpeedRpm
        p1892666644: Global_Variables_Param.sRecData.rSpeedRpm
        p1755163831: rPressure
        p1791247317: sRecData.rPressure
        p338671338: Global_Variables_Param.sRecData.rPressure
        Columns.Column.[2].Template: OnMouseDown: write the text variable via Edit
        Columns.Column.[1].Template: OnMouseDown: write the text variable via Edit
        Columns.Column.[0].Template: OnMouseDown: write the text variable via Edit
END_VISUALIZATION

// ---- Visualizations/Demo_Recipe_HMI/THIRDPARTY_HMI.TcVIS
VISUALIZATION THIRDPARTY_HMI  // 920x770
    Rectangle (10,10 380x560), "第三方 触摸屏"
    Rectangle (40,320 335x240)
    Button (70,485 110x55), "切换配方"
        tap Recipe_OtherHMI.H_RecipeLoad
    Button (70,375 110x55), "保存配方"
        tap Recipe_OtherHMI.H_RecipeSave
    Button (220,485 110x55), "配方另存为"
        tap Recipe_OtherHMI.H_RecipeSaveAs
    Rectangle (70,340 275x29), "当前配方号:"
    Rectangle (210,340 135x29), "%i", text variable: Recipe_OtherHMI.H_CurRecipeNum
    Rectangle (70,450 275x29), "读取/另存配方号:"
    Rectangle (210,450 135x29), "%i", text variable: Recipe_OtherHMI.H_SetRecipeNum
        OnMouseDown: write the text variable via Edit
    Ellipse (250,390 25x25), "B", colour toggle: Recipe_OtherHMI.H_RecipeBusy
    Ellipse (280,390 25x25), "D", colour toggle: Recipe_OtherHMI.H_RecipeDone
    Ellipse (310,390 25x25), "E", colour toggle: Recipe_OtherHMI.H_RecipeError
    Ellipse (220,390 25x25), "I", colour toggle: Recipe_OtherHMI.H_RecipeInitialDone
    Rectangle (40,280 335x35), "当前配方名: %s", text variable: Recipe_OtherHMI.H_CurRecName
    Table (175,15 200x240), data array: Recipe_OtherHMI.H_RecipeName
        p2232123230: Recipe_OtherHMI.H_RecipeName[INDEX]
        Columns.Column.[0].Template: OnMouseDown: write the text variable via Edit
    Rectangle (415,35 375x190), "读取时，把配方名数组中对应设定配方号的名字， 读取到当前配方名。 另存时，把配方名数组中，对应的当前配方名， 另存到设定的配方号对应的名字。 另存后，再在数组中修改对应配方号的名字"
    Rectangle (415,340 375x190), "说明： I：初始化完成 B：读写配方中 D：读写完成 E：读写错误 保存：当前参数保存到当前配方号中。 切换、读取：读取设定的配方号文件。 另存：当前参数另存到设定的配方号文件。"
    Button (15,585 155x45), "第三方触摸屏"
        OnMouseClick: execute { P099_Call_Recipe.iHMI := 2; }
    Rectangle (195,590 725x180), "默认是CE控制器，如果是非CE控制器（WIN7，WIN10），把功能块接口：bRunOnCeDevice 改为FALSE 配方保存默认路径是（在功能块接口：sgFilePath 修改路径） CE系统： \Hard Disk\Data\Recipe 非CE系统：C:\Data\Recipe 文件保存默认路径是（在功能块接口：sgFilePath 修改路径） CE系统： \Hard Disk\Data\Machine 非CE系统：C:\Data\Machine 默认的文件类型是XML（在功能块接口：eFileType 修改类型）"
    Table (420,210 370x70), data array: Global_Variables_Param.sRecData
        p1755163831: rPressure
        p1791247317: Global_Variables_Param.sRecData.rPressure
        p2232123230: rSpeedRpm
        p3854506369: Global_Variables_Param.sRecData.rSpeedRpm
        p511219082: rTemp
        p1892666644: Global_Variables_Param.sRecData.rTemp
        Columns.Column.[0].Template: OnMouseDown: write the text variable via Edit
        Columns.Column.[1].Template: OnMouseDown: write the text variable via Edit
        Columns.Column.[2].Template: OnMouseDown: write the text variable via Edit
    Button (15,640 155x45), "无触摸屏"
        OnMouseClick: execute { P099_Call_Recipe.iHMI := 0; }
END_VISUALIZATION
